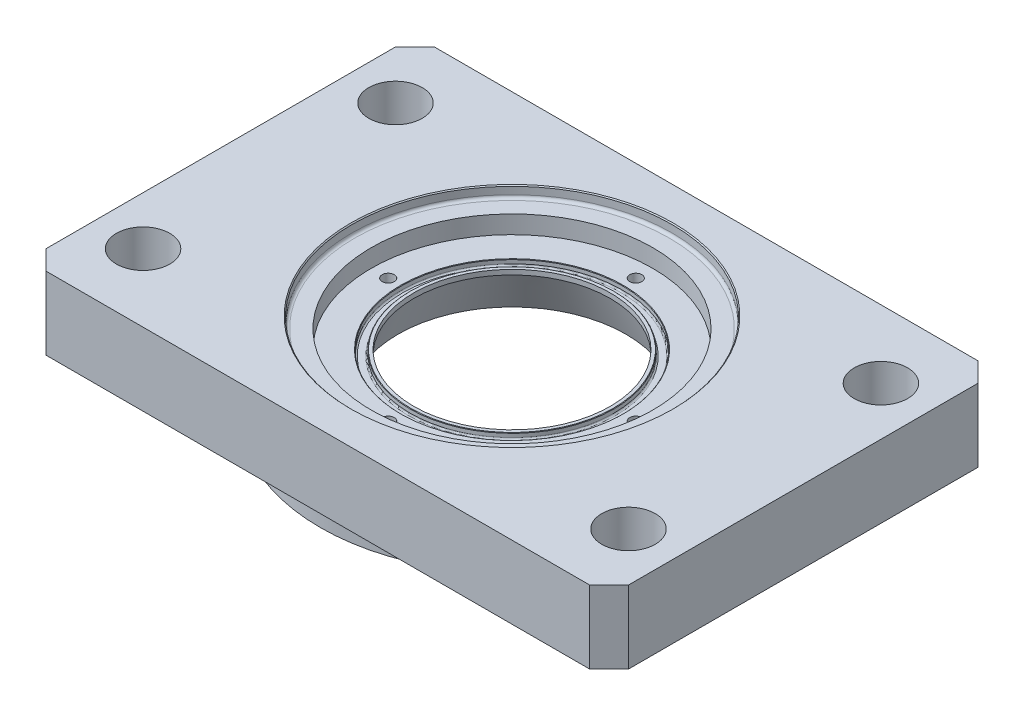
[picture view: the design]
ISO-10303-21;
HEADER;
FILE_DESCRIPTION(('STEP AP214'),'2;1');
FILE_NAME('part.step','',(''),(''),'','','');
FILE_SCHEMA(('AUTOMOTIVE_DESIGN { 1 0 10303 214 1 1 1 1 }'));
ENDSEC;
DATA;
#1=APPLICATION_CONTEXT('core data for automotive mechanical design processes');
#2=APPLICATION_PROTOCOL_DEFINITION('international standard','automotive_design',2000,#1);
#3=PRODUCT_CONTEXT('',#1,'mechanical');
#4=PRODUCT('Part','Part','',(#3));
#5=PRODUCT_RELATED_PRODUCT_CATEGORY('part','',(#4));
#6=PRODUCT_DEFINITION_FORMATION('','',#4);
#7=PRODUCT_DEFINITION_CONTEXT('part definition',#1,'design');
#8=PRODUCT_DEFINITION('design','',#6,#7);
#9=PRODUCT_DEFINITION_SHAPE('','',#8);
#10=(LENGTH_UNIT() NAMED_UNIT(*) SI_UNIT(.MILLI.,.METRE.));
#11=(NAMED_UNIT(*) PLANE_ANGLE_UNIT() SI_UNIT($,.RADIAN.));
#12=(NAMED_UNIT(*) SI_UNIT($,.STERADIAN.) SOLID_ANGLE_UNIT());
#13=UNCERTAINTY_MEASURE_WITH_UNIT(LENGTH_MEASURE(1.E-05),#10,'distance_accuracy_value','');
#14=(GEOMETRIC_REPRESENTATION_CONTEXT(3) GLOBAL_UNCERTAINTY_ASSIGNED_CONTEXT((#13)) GLOBAL_UNIT_ASSIGNED_CONTEXT((#10,
#11,#12)) REPRESENTATION_CONTEXT('',''));
#15=CARTESIAN_POINT('',(0.,0.,0.));
#16=DIRECTION('',(0.,0.,1.));
#17=DIRECTION('',(1.,0.,0.));
#18=AXIS2_PLACEMENT_3D('',#15,#16,#17);
#19=CARTESIAN_POINT('',(25.5,4.386370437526,0.));
#20=DIRECTION('',(0.,1.,0.));
#21=DIRECTION('',(0.,0.,1.));
#22=AXIS2_PLACEMENT_3D('',#19,#20,#21);
#23=CYLINDRICAL_SURFACE('',#22,1.5);
#24=CARTESIAN_POINT('',(25.5,7.,0.));
#25=DIRECTION('',(0.,1.,0.));
#26=DIRECTION('',(0.,0.,1.));
#27=AXIS2_PLACEMENT_3D('',#24,#25,#26);
#28=CIRCLE('',#27,1.5);
#29=CARTESIAN_POINT('',(25.5,7.,1.5));
#30=VERTEX_POINT('',#29);
#31=EDGE_CURVE('P0_E11',#30,#30,#28,.T.);
#32=ORIENTED_EDGE('',*,*,#31,.T.);
#33=EDGE_LOOP('',(#32));
#34=FACE_BOUND('',#33,.T.);
#35=CARTESIAN_POINT('',(25.5,12.,0.));
#36=DIRECTION('',(0.,1.,0.));
#37=DIRECTION('',(0.,0.,1.));
#38=AXIS2_PLACEMENT_3D('',#35,#36,#37);
#39=CIRCLE('',#38,1.5);
#40=CARTESIAN_POINT('',(25.5,12.,1.5));
#41=VERTEX_POINT('',#40);
#42=EDGE_CURVE('P0_E23',#41,#41,#39,.F.);
#43=ORIENTED_EDGE('',*,*,#42,.T.);
#44=EDGE_LOOP('',(#43));
#45=FACE_BOUND('',#44,.T.);
#46=ADVANCED_FACE('P0_F16',(#34,#45),#23,.T.);
#47=CARTESIAN_POINT('',(25.5,7.,0.));
#48=DIRECTION('',(0.,1.,0.));
#49=DIRECTION('',(0.,0.,1.));
#50=AXIS2_PLACEMENT_3D('',#47,#48,#49);
#51=PLANE('',#50);
#52=CARTESIAN_POINT('',(24.25,7.,0.));
#53=CARTESIAN_POINT('',(24.2502025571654,7.,-0.238673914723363));
#54=CARTESIAN_POINT('',(24.337764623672,7.,-0.460118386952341));
#55=CARTESIAN_POINT('',(24.4327647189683,7.,-0.700373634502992));
#56=CARTESIAN_POINT('',(24.6161165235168,7.,-0.883883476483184));
#57=CARTESIAN_POINT('',(24.7987234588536,7.,-1.06664780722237));
#58=CARTESIAN_POINT('',(25.0398816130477,7.,-1.16223537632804));
#59=CARTESIAN_POINT('',(25.2610474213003,7.,-1.24989860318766));
#60=CARTESIAN_POINT('',(25.5,7.,-1.25));
#61=CARTESIAN_POINT('',(25.7379063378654,7.,-1.25010095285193));
#62=CARTESIAN_POINT('',(25.9601183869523,7.,-1.16223537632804));
#63=CARTESIAN_POINT('',(26.2003736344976,7.,-1.06723528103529));
#64=CARTESIAN_POINT('',(26.3838834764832,7.,-0.883883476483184));
#65=CARTESIAN_POINT('',(26.5666478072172,7.,-0.701276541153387));
#66=CARTESIAN_POINT('',(26.662235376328,7.,-0.460118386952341));
#67=CARTESIAN_POINT('',(26.7497969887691,7.,-0.239208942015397));
#68=CARTESIAN_POINT('',(26.75,7.,0.));
#69=B_SPLINE_CURVE_WITH_KNOTS('',2,(#52,#53,#54,#55,#56,#57,#58,#59,#60,#61,#62,#63,#64,#65,#66,
#67,#68),.UNSPECIFIED.,.F.,.F.,(3,2,2,2,2,2,2,2,3),(0.,0.125,0.25,0.375,0.5,0.625,0.75,0.875,
1.),.UNSPECIFIED.);
#70=CARTESIAN_POINT('',(24.25,7.,0.));
#71=VERTEX_POINT('',#70);
#72=CARTESIAN_POINT('',(26.75,7.,0.));
#73=VERTEX_POINT('',#72);
#74=EDGE_CURVE('P0_E27',#71,#73,#69,.T.);
#75=ORIENTED_EDGE('',*,*,#74,.F.);
#76=CARTESIAN_POINT('',(26.75,7.,0.));
#77=CARTESIAN_POINT('',(26.7497974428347,7.,0.238673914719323));
#78=CARTESIAN_POINT('',(26.662235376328,7.,0.460118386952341));
#79=CARTESIAN_POINT('',(26.5672352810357,7.,0.700373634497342));
#80=CARTESIAN_POINT('',(26.3838834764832,7.,0.883883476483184));
#81=CARTESIAN_POINT('',(26.2012765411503,7.,1.06664780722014));
#82=CARTESIAN_POINT('',(25.9601183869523,7.,1.16223537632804));
#83=CARTESIAN_POINT('',(25.7389525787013,7.,1.24989860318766));
#84=CARTESIAN_POINT('',(25.5,7.,1.25));
#85=CARTESIAN_POINT('',(25.2620936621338,7.,1.25010095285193));
#86=CARTESIAN_POINT('',(25.0398816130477,7.,1.16223537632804));
#87=CARTESIAN_POINT('',(24.7996263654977,7.,1.06723528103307));
#88=CARTESIAN_POINT('',(24.6161165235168,7.,0.883883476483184));
#89=CARTESIAN_POINT('',(24.4333521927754,7.,0.701276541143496));
#90=CARTESIAN_POINT('',(24.337764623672,7.,0.460118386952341));
#91=CARTESIAN_POINT('',(24.2502030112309,7.,0.239208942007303));
#92=CARTESIAN_POINT('',(24.25,7.,0.));
#93=B_SPLINE_CURVE_WITH_KNOTS('',2,(#76,#77,#78,#79,#80,#81,#82,#83,#84,#85,#86,#87,#88,#89,#90,
#91,#92),.UNSPECIFIED.,.F.,.F.,(3,2,2,2,2,2,2,2,3),(0.,0.125,0.25,0.375,0.5,0.625,0.75,0.875,
1.),.UNSPECIFIED.);
#94=EDGE_CURVE('P0_E32',#73,#71,#93,.T.);
#95=ORIENTED_EDGE('',*,*,#94,.F.);
#96=EDGE_LOOP('',(#75,#95));
#97=FACE_BOUND('',#96,.T.);
#98=ORIENTED_EDGE('',*,*,#31,.F.);
#99=EDGE_LOOP('',(#98));
#100=FACE_BOUND('',#99,.T.);
#101=ADVANCED_FACE('P0_F17',(#97,#100),#51,.F.);
#102=OPEN_SHELL('',(#46,#101));
#103=SHELL_BASED_SURFACE_MODEL('P0_B1',(#102));
#104=CARTESIAN_POINT('',(0.,12.,0.));
#105=DIRECTION('',(0.,1.,0.));
#106=DIRECTION('',(0.,0.,1.));
#107=AXIS2_PLACEMENT_3D('',#104,#105,#106);
#108=CYLINDRICAL_SURFACE('',#107,21.);
#109=CARTESIAN_POINT('',(0.,11.15,0.));
#110=DIRECTION('',(0.,1.,0.));
#111=DIRECTION('',(0.999942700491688,0.,0.0107049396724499));
#112=AXIS2_PLACEMENT_3D('',#109,#110,#111);
#113=CIRCLE('',#112,21.);
#114=CARTESIAN_POINT('',(20.9987967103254,11.15,0.224803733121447));
#115=VERTEX_POINT('',#114);
#116=EDGE_CURVE('P1_E308',#115,#115,#113,.T.);
#117=ORIENTED_EDGE('',*,*,#116,.T.);
#118=EDGE_LOOP('',(#117));
#119=FACE_BOUND('',#118,.T.);
#120=CARTESIAN_POINT('',(0.,11.9,0.));
#121=DIRECTION('',(0.,-1.,0.));
#122=DIRECTION('',(0.,0.,-1.));
#123=AXIS2_PLACEMENT_3D('',#120,#121,#122);
#124=CIRCLE('',#123,21.);
#125=CARTESIAN_POINT('',(0.,11.9,-21.));
#126=VERTEX_POINT('',#125);
#127=EDGE_CURVE('P1_E116',#126,#126,#124,.F.);
#128=ORIENTED_EDGE('',*,*,#127,.F.);
#129=EDGE_LOOP('',(#128));
#130=FACE_BOUND('',#129,.T.);
#131=ADVANCED_FACE('P1_F16',(#119,#130),#108,.T.);
#132=CARTESIAN_POINT('',(0.,11.15,0.));
#133=DIRECTION('',(0.,1.,0.));
#134=DIRECTION('',(0.999942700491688,0.,0.0107049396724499));
#135=AXIS2_PLACEMENT_3D('',#132,#133,#134);
#136=TOROIDAL_SURFACE('',#135,21.3,0.3);
#137=ORIENTED_EDGE('',*,*,#116,.F.);
#138=EDGE_LOOP('',(#137));
#139=FACE_BOUND('',#138,.T.);
#140=CARTESIAN_POINT('',(0.,10.85,0.));
#141=DIRECTION('',(0.,1.,0.));
#142=DIRECTION('',(-1.,0.,0.));
#143=AXIS2_PLACEMENT_3D('',#140,#141,#142);
#144=CIRCLE('',#143,21.3);
#145=CARTESIAN_POINT('',(21.3,10.85,0.));
#146=VERTEX_POINT('',#145);
#147=CARTESIAN_POINT('',(-21.3,10.85,0.));
#148=VERTEX_POINT('',#147);
#149=EDGE_CURVE('P1_E112',#146,#148,#144,.F.);
#150=ORIENTED_EDGE('',*,*,#149,.F.);
#151=CARTESIAN_POINT('',(0.,10.85,0.));
#152=DIRECTION('',(0.,1.,0.));
#153=DIRECTION('',(1.,0.,0.));
#154=AXIS2_PLACEMENT_3D('',#151,#152,#153);
#155=CIRCLE('',#154,21.3);
#156=EDGE_CURVE('P1_E109',#148,#146,#155,.F.);
#157=ORIENTED_EDGE('',*,*,#156,.F.);
#158=EDGE_LOOP('',(#150,#157));
#159=FACE_BOUND('',#158,.T.);
#160=ADVANCED_FACE('P1_F113',(#139,#159),#136,.F.);
#161=CARTESIAN_POINT('',(0.,11.9,0.));
#162=DIRECTION('',(0.,-1.,0.));
#163=DIRECTION('',(0.,0.,-1.));
#164=AXIS2_PLACEMENT_3D('',#161,#162,#163);
#165=CONICAL_SURFACE('',#164,21.,0.785398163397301);
#166=ORIENTED_EDGE('',*,*,#127,.T.);
#167=EDGE_LOOP('',(#166));
#168=FACE_BOUND('',#167,.T.);
#169=CARTESIAN_POINT('',(0.,12.,0.));
#170=DIRECTION('',(0.,-1.,0.));
#171=DIRECTION('',(0.,0.,-1.));
#172=AXIS2_PLACEMENT_3D('',#169,#170,#171);
#173=CIRCLE('',#172,20.9);
#174=CARTESIAN_POINT('',(0.,12.,-20.9));
#175=VERTEX_POINT('',#174);
#176=EDGE_CURVE('P1_E121',#175,#175,#173,.T.);
#177=ORIENTED_EDGE('',*,*,#176,.T.);
#178=EDGE_LOOP('',(#177));
#179=FACE_BOUND('',#178,.T.);
#180=ADVANCED_FACE('P1_F142',(#168,#179),#165,.T.);
#181=CARTESIAN_POINT('',(0.,10.85,0.));
#182=DIRECTION('',(0.,1.,0.));
#183=DIRECTION('',(0.,0.,1.));
#184=AXIS2_PLACEMENT_3D('',#181,#182,#183);
#185=PLANE('',#184);
#186=ORIENTED_EDGE('',*,*,#149,.T.);
#187=ORIENTED_EDGE('',*,*,#156,.T.);
#188=EDGE_LOOP('',(#186,#187));
#189=FACE_BOUND('',#188,.T.);
#190=CARTESIAN_POINT('',(0.,10.85,0.));
#191=DIRECTION('',(0.,-1.,0.));
#192=DIRECTION('',(1.,0.,0.));
#193=AXIS2_PLACEMENT_3D('',#190,#191,#192);
#194=CIRCLE('',#193,22.55);
#195=CARTESIAN_POINT('',(-22.55,10.85,0.));
#196=VERTEX_POINT('',#195);
#197=CARTESIAN_POINT('',(22.55,10.85,0.));
#198=VERTEX_POINT('',#197);
#199=EDGE_CURVE('P1_E162',#196,#198,#194,.F.);
#200=ORIENTED_EDGE('',*,*,#199,.T.);
#201=CARTESIAN_POINT('',(0.,10.85,0.));
#202=DIRECTION('',(0.,-1.,0.));
#203=DIRECTION('',(-1.,0.,0.));
#204=AXIS2_PLACEMENT_3D('',#201,#202,#203);
#205=CIRCLE('',#204,22.55);
#206=EDGE_CURVE('P1_E161',#198,#196,#205,.F.);
#207=ORIENTED_EDGE('',*,*,#206,.T.);
#208=EDGE_LOOP('',(#200,#207));
#209=FACE_BOUND('',#208,.T.);
#210=ADVANCED_FACE('P1_F119',(#189,#209),#185,.T.);
#211=CARTESIAN_POINT('',(0.,12.,0.));
#212=DIRECTION('',(0.,-1.,0.));
#213=DIRECTION('',(0.,0.,-1.));
#214=AXIS2_PLACEMENT_3D('',#211,#212,#213);
#215=PLANE('',#214);
#216=CARTESIAN_POINT('',(0.,12.,0.));
#217=DIRECTION('',(0.,1.,0.));
#218=DIRECTION('',(0.,0.,1.));
#219=AXIS2_PLACEMENT_3D('',#216,#217,#218);
#220=CIRCLE('',#219,20.25);
#221=CARTESIAN_POINT('',(0.,12.,20.25));
#222=VERTEX_POINT('',#221);
#223=EDGE_CURVE('P1_E166',#222,#222,#220,.F.);
#224=ORIENTED_EDGE('',*,*,#223,.T.);
#225=EDGE_LOOP('',(#224));
#226=FACE_BOUND('',#225,.T.);
#227=ORIENTED_EDGE('',*,*,#176,.F.);
#228=EDGE_LOOP('',(#227));
#229=FACE_BOUND('',#228,.T.);
#230=ADVANCED_FACE('P1_F141',(#226,#229),#215,.F.);
#231=CARTESIAN_POINT('',(0.,11.15,0.));
#232=DIRECTION('',(0.,1.,0.));
#233=DIRECTION('',(0.999902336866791,0.,-0.0139755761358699));
#234=AXIS2_PLACEMENT_3D('',#231,#232,#233);
#235=TOROIDAL_SURFACE('',#234,22.55,0.3);
#236=CARTESIAN_POINT('',(0.,11.15,0.));
#237=DIRECTION('',(0.,1.,0.));
#238=DIRECTION('',(0.,0.,1.));
#239=AXIS2_PLACEMENT_3D('',#236,#237,#238);
#240=CIRCLE('',#239,22.85);
#241=CARTESIAN_POINT('',(0.,11.15,22.85));
#242=VERTEX_POINT('',#241);
#243=EDGE_CURVE('P1_E168',#242,#242,#240,.T.);
#244=ORIENTED_EDGE('',*,*,#243,.T.);
#245=EDGE_LOOP('',(#244));
#246=FACE_BOUND('',#245,.T.);
#247=ORIENTED_EDGE('',*,*,#206,.F.);
#248=ORIENTED_EDGE('',*,*,#199,.F.);
#249=EDGE_LOOP('',(#247,#248));
#250=FACE_BOUND('',#249,.T.);
#251=ADVANCED_FACE('P1_F165',(#246,#250),#235,.F.);
#252=CARTESIAN_POINT('',(0.,2.55,0.));
#253=DIRECTION('',(0.,1.,0.));
#254=DIRECTION('',(0.,0.,1.));
#255=AXIS2_PLACEMENT_3D('',#252,#253,#254);
#256=CYLINDRICAL_SURFACE('',#255,20.25);
#257=CARTESIAN_POINT('',(0.,10.9999999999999,0.));
#258=DIRECTION('',(0.,-1.,0.));
#259=DIRECTION('',(-1.,0.,0.));
#260=AXIS2_PLACEMENT_3D('',#257,#258,#259);
#261=CIRCLE('',#260,20.2499999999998);
#262=CARTESIAN_POINT('',(-20.2499999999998,10.9999999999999,0.));
#263=VERTEX_POINT('',#262);
#264=EDGE_CURVE('P1_E173',#263,#263,#261,.T.);
#265=ORIENTED_EDGE('',*,*,#264,.T.);
#266=EDGE_LOOP('',(#265));
#267=FACE_BOUND('',#266,.T.);
#268=ORIENTED_EDGE('',*,*,#223,.F.);
#269=EDGE_LOOP('',(#268));
#270=FACE_BOUND('',#269,.T.);
#271=ADVANCED_FACE('P1_F273',(#267,#270),#256,.F.);
#272=CARTESIAN_POINT('',(-25.5,5.49999999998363,0.));
#273=DIRECTION('',(0.,1.,0.));
#274=DIRECTION('',(0.,0.,1.));
#275=AXIS2_PLACEMENT_3D('',#272,#273,#274);
#276=CONICAL_SURFACE('',#275,1.24999999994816,1.0297442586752);
#277=CARTESIAN_POINT('',(-25.5,5.5,0.));
#278=DIRECTION('',(0.,1.,0.));
#279=DIRECTION('',(0.,0.,1.));
#280=AXIS2_PLACEMENT_3D('',#277,#278,#279);
#281=CIRCLE('',#280,1.25);
#282=CARTESIAN_POINT('',(-25.5,5.5,1.25));
#283=VERTEX_POINT('',#282);
#284=EDGE_CURVE('P1_E264',#283,#283,#281,.T.);
#285=ORIENTED_EDGE('',*,*,#284,.T.);
#286=EDGE_LOOP('',(#285));
#287=FACE_BOUND('',#286,.T.);
#288=CARTESIAN_POINT('',(-25.4999999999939,4.74892422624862,0.));
#289=VERTEX_POINT('',#288);
#290=VERTEX_LOOP('',#289);
#291=FACE_BOUND('',#290,.T.);
#292=ADVANCED_FACE('P1_F656',(#287,#291),#276,.F.);
#293=CARTESIAN_POINT('',(0.,5.49999999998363,25.5));
#294=DIRECTION('',(0.,1.,0.));
#295=DIRECTION('',(0.,0.,1.));
#296=AXIS2_PLACEMENT_3D('',#293,#294,#295);
#297=CONICAL_SURFACE('',#296,1.24999999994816,1.0297442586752);
#298=CARTESIAN_POINT('',(0.,5.5,25.5));
#299=DIRECTION('',(0.,1.,0.));
#300=DIRECTION('',(0.,0.,1.));
#301=AXIS2_PLACEMENT_3D('',#298,#299,#300);
#302=CIRCLE('',#301,1.25);
#303=CARTESIAN_POINT('',(0.,5.5,26.75));
#304=VERTEX_POINT('',#303);
#305=EDGE_CURVE('P1_E261',#304,#304,#302,.T.);
#306=ORIENTED_EDGE('',*,*,#305,.T.);
#307=EDGE_LOOP('',(#306));
#308=FACE_BOUND('',#307,.T.);
#309=CARTESIAN_POINT('',(0.,4.74892422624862,25.4999999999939));
#310=VERTEX_POINT('',#309);
#311=VERTEX_LOOP('',#310);
#312=FACE_BOUND('',#311,.T.);
#313=ADVANCED_FACE('P1_F652',(#308,#312),#297,.F.);
#314=CARTESIAN_POINT('',(25.5,5.49999999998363,0.));
#315=DIRECTION('',(0.,1.,0.));
#316=DIRECTION('',(0.,0.,1.));
#317=AXIS2_PLACEMENT_3D('',#314,#315,#316);
#318=CONICAL_SURFACE('',#317,1.24999999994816,1.0297442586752);
#319=CARTESIAN_POINT('',(25.5,5.5,0.));
#320=DIRECTION('',(0.,1.,0.));
#321=DIRECTION('',(0.,0.,1.));
#322=AXIS2_PLACEMENT_3D('',#319,#320,#321);
#323=CIRCLE('',#322,1.25);
#324=CARTESIAN_POINT('',(25.5,5.5,1.25));
#325=VERTEX_POINT('',#324);
#326=EDGE_CURVE('P1_E258',#325,#325,#323,.T.);
#327=ORIENTED_EDGE('',*,*,#326,.T.);
#328=EDGE_LOOP('',(#327));
#329=FACE_BOUND('',#328,.T.);
#330=CARTESIAN_POINT('',(25.4999999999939,4.74892422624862,0.));
#331=VERTEX_POINT('',#330);
#332=VERTEX_LOOP('',#331);
#333=FACE_BOUND('',#332,.T.);
#334=ADVANCED_FACE('P1_F655',(#329,#333),#318,.F.);
#335=CARTESIAN_POINT('',(0.,5.49999999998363,-25.5));
#336=DIRECTION('',(0.,1.,0.));
#337=DIRECTION('',(0.,0.,1.));
#338=AXIS2_PLACEMENT_3D('',#335,#336,#337);
#339=CONICAL_SURFACE('',#338,1.24999999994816,1.0297442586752);
#340=CARTESIAN_POINT('',(0.,5.5,-25.5));
#341=DIRECTION('',(0.,1.,0.));
#342=DIRECTION('',(0.,0.,1.));
#343=AXIS2_PLACEMENT_3D('',#340,#341,#342);
#344=CIRCLE('',#343,1.25);
#345=CARTESIAN_POINT('',(0.,5.5,-24.25));
#346=VERTEX_POINT('',#345);
#347=EDGE_CURVE('P1_E255',#346,#346,#344,.T.);
#348=ORIENTED_EDGE('',*,*,#347,.T.);
#349=EDGE_LOOP('',(#348));
#350=FACE_BOUND('',#349,.T.);
#351=CARTESIAN_POINT('',(0.,4.74892422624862,-25.4999999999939));
#352=VERTEX_POINT('',#351);
#353=VERTEX_LOOP('',#352);
#354=FACE_BOUND('',#353,.T.);
#355=ADVANCED_FACE('P1_F414',(#350,#354),#339,.F.);
#356=CARTESIAN_POINT('',(0.,12.,0.));
#357=DIRECTION('',(0.,1.,0.));
#358=DIRECTION('',(0.,0.,1.));
#359=AXIS2_PLACEMENT_3D('',#356,#357,#358);
#360=CYLINDRICAL_SURFACE('',#359,22.85);
#361=ORIENTED_EDGE('',*,*,#243,.F.);
#362=EDGE_LOOP('',(#361));
#363=FACE_BOUND('',#362,.T.);
#364=CARTESIAN_POINT('',(0.,11.9,0.));
#365=DIRECTION('',(0.,1.,0.));
#366=DIRECTION('',(0.,0.,-1.));
#367=AXIS2_PLACEMENT_3D('',#364,#365,#366);
#368=CIRCLE('',#367,22.85);
#369=CARTESIAN_POINT('',(0.,11.9,-22.85));
#370=VERTEX_POINT('',#369);
#371=EDGE_CURVE('P1_E247',#370,#370,#368,.T.);
#372=ORIENTED_EDGE('',*,*,#371,.T.);
#373=EDGE_LOOP('',(#372));
#374=FACE_BOUND('',#373,.T.);
#375=ADVANCED_FACE('P1_F403',(#363,#374),#360,.F.);
#376=CARTESIAN_POINT('',(0.,3.0000000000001,0.));
#377=DIRECTION('',(0.,-1.,0.));
#378=DIRECTION('',(0.,0.,-1.));
#379=AXIS2_PLACEMENT_3D('',#376,#377,#378);
#380=CONICAL_SURFACE('',#379,23.4822098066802,0.38397243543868);
#381=ORIENTED_EDGE('',*,*,#264,.F.);
#382=EDGE_LOOP('',(#381));
#383=FACE_BOUND('',#382,.T.);
#384=CARTESIAN_POINT('',(0.,3.0000000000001,0.));
#385=DIRECTION('',(0.,-1.,0.));
#386=DIRECTION('',(0.,0.,-1.));
#387=AXIS2_PLACEMENT_3D('',#384,#385,#386);
#388=CIRCLE('',#387,23.4822098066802);
#389=CARTESIAN_POINT('',(0.,3.0000000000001,-23.4822098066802));
#390=VERTEX_POINT('',#389);
#391=EDGE_CURVE('P1_E177',#390,#390,#388,.F.);
#392=ORIENTED_EDGE('',*,*,#391,.F.);
#393=EDGE_LOOP('',(#392));
#394=FACE_BOUND('',#393,.T.);
#395=ADVANCED_FACE('P1_F400',(#383,#394),#380,.F.);
#396=CARTESIAN_POINT('',(-25.5,4.386370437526,0.));
#397=DIRECTION('',(0.,1.,0.));
#398=DIRECTION('',(0.,0.,1.));
#399=AXIS2_PLACEMENT_3D('',#396,#397,#398);
#400=CYLINDRICAL_SURFACE('',#399,1.25);
#401=ORIENTED_EDGE('',*,*,#284,.F.);
#402=EDGE_LOOP('',(#401));
#403=FACE_BOUND('',#402,.T.);
#404=CARTESIAN_POINT('',(-25.5,12.,0.));
#405=DIRECTION('',(0.,1.,0.));
#406=DIRECTION('',(0.,0.,1.));
#407=AXIS2_PLACEMENT_3D('',#404,#405,#406);
#408=CIRCLE('',#407,1.25);
#409=CARTESIAN_POINT('',(-25.5,12.,1.25));
#410=VERTEX_POINT('',#409);
#411=EDGE_CURVE('P1_E390',#410,#410,#408,.T.);
#412=ORIENTED_EDGE('',*,*,#411,.T.);
#413=EDGE_LOOP('',(#412));
#414=FACE_BOUND('',#413,.T.);
#415=ADVANCED_FACE('P1_F402',(#403,#414),#400,.F.);
#416=CARTESIAN_POINT('',(0.,4.386370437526,25.5));
#417=DIRECTION('',(0.,1.,0.));
#418=DIRECTION('',(0.,0.,1.));
#419=AXIS2_PLACEMENT_3D('',#416,#417,#418);
#420=CYLINDRICAL_SURFACE('',#419,1.25);
#421=ORIENTED_EDGE('',*,*,#305,.F.);
#422=EDGE_LOOP('',(#421));
#423=FACE_BOUND('',#422,.T.);
#424=CARTESIAN_POINT('',(0.,12.,25.5));
#425=DIRECTION('',(0.,1.,0.));
#426=DIRECTION('',(0.,0.,1.));
#427=AXIS2_PLACEMENT_3D('',#424,#425,#426);
#428=CIRCLE('',#427,1.25);
#429=CARTESIAN_POINT('',(0.,12.,26.75));
#430=VERTEX_POINT('',#429);
#431=EDGE_CURVE('P1_E388',#430,#430,#428,.T.);
#432=ORIENTED_EDGE('',*,*,#431,.T.);
#433=EDGE_LOOP('',(#432));
#434=FACE_BOUND('',#433,.T.);
#435=ADVANCED_FACE('P1_F411',(#423,#434),#420,.F.);
#436=CARTESIAN_POINT('',(25.5,4.386370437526,0.));
#437=DIRECTION('',(0.,1.,0.));
#438=DIRECTION('',(0.,0.,1.));
#439=AXIS2_PLACEMENT_3D('',#436,#437,#438);
#440=CYLINDRICAL_SURFACE('',#439,1.25);
#441=ORIENTED_EDGE('',*,*,#326,.F.);
#442=EDGE_LOOP('',(#441));
#443=FACE_BOUND('',#442,.T.);
#444=CARTESIAN_POINT('',(25.5,12.,0.));
#445=DIRECTION('',(0.,1.,0.));
#446=DIRECTION('',(0.,0.,1.));
#447=AXIS2_PLACEMENT_3D('',#444,#445,#446);
#448=CIRCLE('',#447,1.25);
#449=CARTESIAN_POINT('',(25.5,12.,1.25));
#450=VERTEX_POINT('',#449);
#451=EDGE_CURVE('P1_E385',#450,#450,#448,.T.);
#452=ORIENTED_EDGE('',*,*,#451,.T.);
#453=EDGE_LOOP('',(#452));
#454=FACE_BOUND('',#453,.T.);
#455=ADVANCED_FACE('P1_F633',(#443,#454),#440,.F.);
#456=CARTESIAN_POINT('',(0.,4.386370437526,-25.5));
#457=DIRECTION('',(0.,1.,0.));
#458=DIRECTION('',(0.,0.,1.));
#459=AXIS2_PLACEMENT_3D('',#456,#457,#458);
#460=CYLINDRICAL_SURFACE('',#459,1.25);
#461=ORIENTED_EDGE('',*,*,#347,.F.);
#462=EDGE_LOOP('',(#461));
#463=FACE_BOUND('',#462,.T.);
#464=CARTESIAN_POINT('',(0.,12.,-25.5));
#465=DIRECTION('',(0.,1.,0.));
#466=DIRECTION('',(0.,0.,1.));
#467=AXIS2_PLACEMENT_3D('',#464,#465,#466);
#468=CIRCLE('',#467,1.25);
#469=CARTESIAN_POINT('',(0.,12.,-24.25));
#470=VERTEX_POINT('',#469);
#471=EDGE_CURVE('P1_E382',#470,#470,#468,.T.);
#472=ORIENTED_EDGE('',*,*,#471,.T.);
#473=EDGE_LOOP('',(#472));
#474=FACE_BOUND('',#473,.T.);
#475=ADVANCED_FACE('P1_F629',(#463,#474),#460,.F.);
#476=CARTESIAN_POINT('',(0.,12.,0.));
#477=DIRECTION('',(0.,1.,0.));
#478=DIRECTION('',(-1.,0.,0.));
#479=AXIS2_PLACEMENT_3D('',#476,#477,#478);
#480=CONICAL_SURFACE('',#479,22.95,0.785398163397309);
#481=ORIENTED_EDGE('',*,*,#371,.F.);
#482=EDGE_LOOP('',(#481));
#483=FACE_BOUND('',#482,.T.);
#484=CARTESIAN_POINT('',(0.,12.,0.));
#485=DIRECTION('',(0.,1.,0.));
#486=DIRECTION('',(-1.,0.,0.));
#487=AXIS2_PLACEMENT_3D('',#484,#485,#486);
#488=CIRCLE('',#487,22.95);
#489=CARTESIAN_POINT('',(-22.95,12.,0.));
#490=VERTEX_POINT('',#489);
#491=EDGE_CURVE('P1_E379',#490,#490,#488,.T.);
#492=ORIENTED_EDGE('',*,*,#491,.T.);
#493=EDGE_LOOP('',(#492));
#494=FACE_BOUND('',#493,.T.);
#495=ADVANCED_FACE('P1_F626',(#483,#494),#480,.F.);
#496=CARTESIAN_POINT('',(0.,3.,0.));
#497=DIRECTION('',(0.,-1.,0.));
#498=DIRECTION('',(0.,0.,-1.));
#499=AXIS2_PLACEMENT_3D('',#496,#497,#498);
#500=PLANE('',#499);
#501=ORIENTED_EDGE('',*,*,#391,.T.);
#502=EDGE_LOOP('',(#501));
#503=FACE_BOUND('',#502,.T.);
#504=CARTESIAN_POINT('',(0.,3.,0.));
#505=DIRECTION('',(0.,-1.,0.));
#506=DIRECTION('',(0.,0.,-1.));
#507=AXIS2_PLACEMENT_3D('',#504,#505,#506);
#508=CIRCLE('',#507,38.);
#509=CARTESIAN_POINT('',(0.,3.,-38.));
#510=VERTEX_POINT('',#509);
#511=EDGE_CURVE('P1_E376',#510,#510,#508,.T.);
#512=ORIENTED_EDGE('',*,*,#511,.T.);
#513=EDGE_LOOP('',(#512));
#514=FACE_BOUND('',#513,.T.);
#515=ADVANCED_FACE('P1_F397',(#503,#514),#500,.T.);
#516=CARTESIAN_POINT('',(0.,12.,0.));
#517=DIRECTION('',(0.,-1.,0.));
#518=DIRECTION('',(0.,0.,-1.));
#519=AXIS2_PLACEMENT_3D('',#516,#517,#518);
#520=PLANE('',#519);
#521=ORIENTED_EDGE('',*,*,#491,.F.);
#522=EDGE_LOOP('',(#521));
#523=FACE_BOUND('',#522,.T.);
#524=ORIENTED_EDGE('',*,*,#471,.F.);
#525=EDGE_LOOP('',(#524));
#526=FACE_BOUND('',#525,.T.);
#527=ORIENTED_EDGE('',*,*,#451,.F.);
#528=EDGE_LOOP('',(#527));
#529=FACE_BOUND('',#528,.T.);
#530=ORIENTED_EDGE('',*,*,#431,.F.);
#531=EDGE_LOOP('',(#530));
#532=FACE_BOUND('',#531,.T.);
#533=ORIENTED_EDGE('',*,*,#411,.F.);
#534=EDGE_LOOP('',(#533));
#535=FACE_BOUND('',#534,.T.);
#536=CARTESIAN_POINT('',(0.,12.,0.));
#537=DIRECTION('',(0.,-1.,0.));
#538=DIRECTION('',(0.,0.,-1.));
#539=AXIS2_PLACEMENT_3D('',#536,#537,#538);
#540=CIRCLE('',#539,29.);
#541=CARTESIAN_POINT('',(0.,12.,-29.));
#542=VERTEX_POINT('',#541);
#543=EDGE_CURVE('P1_E373',#542,#542,#540,.F.);
#544=ORIENTED_EDGE('',*,*,#543,.T.);
#545=EDGE_LOOP('',(#544));
#546=FACE_BOUND('',#545,.T.);
#547=ADVANCED_FACE('P1_F614',(#523,#526,#529,#532,#535,#546),#520,.F.);
#548=CARTESIAN_POINT('',(0.,0.,0.));
#549=DIRECTION('',(0.,-1.,0.));
#550=DIRECTION('',(0.,0.,-1.));
#551=AXIS2_PLACEMENT_3D('',#548,#549,#550);
#552=CYLINDRICAL_SURFACE('',#551,38.);
#553=ORIENTED_EDGE('',*,*,#511,.F.);
#554=EDGE_LOOP('',(#553));
#555=FACE_BOUND('',#554,.T.);
#556=CARTESIAN_POINT('',(0.,0.,0.));
#557=DIRECTION('',(0.,-1.,0.));
#558=DIRECTION('',(0.,0.,-1.));
#559=AXIS2_PLACEMENT_3D('',#556,#557,#558);
#560=CIRCLE('',#559,38.);
#561=CARTESIAN_POINT('',(0.,0.,-38.));
#562=VERTEX_POINT('',#561);
#563=EDGE_CURVE('P1_E370',#562,#562,#560,.T.);
#564=ORIENTED_EDGE('',*,*,#563,.T.);
#565=EDGE_LOOP('',(#564));
#566=FACE_BOUND('',#565,.T.);
#567=ADVANCED_FACE('P1_F609',(#555,#566),#552,.F.);
#568=CARTESIAN_POINT('',(0.,18.,0.));
#569=DIRECTION('',(0.,-1.,0.));
#570=DIRECTION('',(0.,0.,-1.));
#571=AXIS2_PLACEMENT_3D('',#568,#569,#570);
#572=CYLINDRICAL_SURFACE('',#571,29.);
#573=ORIENTED_EDGE('',*,*,#543,.F.);
#574=EDGE_LOOP('',(#573));
#575=FACE_BOUND('',#574,.T.);
#576=CARTESIAN_POINT('',(0.,15.7,0.));
#577=DIRECTION('',(0.,-1.,0.));
#578=DIRECTION('',(0.,0.,-1.));
#579=AXIS2_PLACEMENT_3D('',#576,#577,#578);
#580=CIRCLE('',#579,29.);
#581=CARTESIAN_POINT('',(0.,15.7,-29.));
#582=VERTEX_POINT('',#581);
#583=EDGE_CURVE('P1_E367',#582,#582,#580,.T.);
#584=ORIENTED_EDGE('',*,*,#583,.F.);
#585=EDGE_LOOP('',(#584));
#586=FACE_BOUND('',#585,.T.);
#587=ADVANCED_FACE('P1_F604',(#575,#586),#572,.F.);
#588=CARTESIAN_POINT('',(0.,0.,0.));
#589=DIRECTION('',(0.,1.,0.));
#590=DIRECTION('',(0.,0.,1.));
#591=AXIS2_PLACEMENT_3D('',#588,#589,#590);
#592=PLANE('',#591);
#593=ORIENTED_EDGE('',*,*,#563,.F.);
#594=EDGE_LOOP('',(#593));
#595=FACE_BOUND('',#594,.T.);
#596=CARTESIAN_POINT('',(0.,0.,0.));
#597=DIRECTION('',(0.,-1.,0.));
#598=DIRECTION('',(0.,0.,-1.));
#599=AXIS2_PLACEMENT_3D('',#596,#597,#598);
#600=CIRCLE('',#599,39.5);
#601=CARTESIAN_POINT('',(0.,0.,-39.5));
#602=VERTEX_POINT('',#601);
#603=EDGE_CURVE('P1_E364',#602,#602,#600,.F.);
#604=ORIENTED_EDGE('',*,*,#603,.F.);
#605=EDGE_LOOP('',(#604));
#606=FACE_BOUND('',#605,.T.);
#607=ADVANCED_FACE('P1_F230',(#595,#606),#592,.F.);
#608=CARTESIAN_POINT('',(0.,15.7,0.));
#609=DIRECTION('',(0.,1.,0.));
#610=DIRECTION('',(0.,0.,1.));
#611=AXIS2_PLACEMENT_3D('',#608,#609,#610);
#612=PLANE('',#611);
#613=ORIENTED_EDGE('',*,*,#583,.T.);
#614=EDGE_LOOP('',(#613));
#615=FACE_BOUND('',#614,.T.);
#616=CARTESIAN_POINT('',(0.,15.7,0.));
#617=DIRECTION('',(0.,-1.,0.));
#618=DIRECTION('',(1.,0.,0.));
#619=AXIS2_PLACEMENT_3D('',#616,#617,#618);
#620=CIRCLE('',#619,32.4);
#621=CARTESIAN_POINT('',(-32.4,15.7,0.));
#622=VERTEX_POINT('',#621);
#623=CARTESIAN_POINT('',(32.4,15.7,0.));
#624=VERTEX_POINT('',#623);
#625=EDGE_CURVE('P1_E185',#622,#624,#620,.F.);
#626=ORIENTED_EDGE('',*,*,#625,.T.);
#627=CARTESIAN_POINT('',(0.,15.7,0.));
#628=DIRECTION('',(0.,-1.,0.));
#629=DIRECTION('',(-1.,0.,0.));
#630=AXIS2_PLACEMENT_3D('',#627,#628,#629);
#631=CIRCLE('',#630,32.4);
#632=EDGE_CURVE('P1_E243',#624,#622,#631,.F.);
#633=ORIENTED_EDGE('',*,*,#632,.T.);
#634=EDGE_LOOP('',(#626,#633));
#635=FACE_BOUND('',#634,.T.);
#636=ADVANCED_FACE('P1_F219',(#615,#635),#612,.T.);
#637=CARTESIAN_POINT('',(0.,0.,0.));
#638=DIRECTION('',(0.,-1.,0.));
#639=DIRECTION('',(0.,0.,-1.));
#640=AXIS2_PLACEMENT_3D('',#637,#638,#639);
#641=CYLINDRICAL_SURFACE('',#640,39.5);
#642=CARTESIAN_POINT('',(0.,3.,0.));
#643=DIRECTION('',(0.,-1.,0.));
#644=DIRECTION('',(0.,0.,-1.));
#645=AXIS2_PLACEMENT_3D('',#642,#643,#644);
#646=CIRCLE('',#645,39.5);
#647=CARTESIAN_POINT('',(0.,3.,-39.5));
#648=VERTEX_POINT('',#647);
#649=EDGE_CURVE('P1_E361',#648,#648,#646,.F.);
#650=ORIENTED_EDGE('',*,*,#649,.F.);
#651=EDGE_LOOP('',(#650));
#652=FACE_BOUND('',#651,.T.);
#653=ORIENTED_EDGE('',*,*,#603,.T.);
#654=EDGE_LOOP('',(#653));
#655=FACE_BOUND('',#654,.T.);
#656=ADVANCED_FACE('P1_F229',(#652,#655),#641,.T.);
#657=CARTESIAN_POINT('',(-50.,3.,26.));
#658=DIRECTION('',(0.,1.,0.));
#659=DIRECTION('',(0.,0.,1.));
#660=AXIS2_PLACEMENT_3D('',#657,#658,#659);
#661=CYLINDRICAL_SURFACE('',#660,8.5);
#662=CARTESIAN_POINT('',(-50.,8.,26.));
#663=DIRECTION('',(0.,1.,0.));
#664=DIRECTION('',(0.,0.,1.));
#665=AXIS2_PLACEMENT_3D('',#662,#663,#664);
#666=CIRCLE('',#665,8.5);
#667=CARTESIAN_POINT('',(-50.,8.,34.5));
#668=VERTEX_POINT('',#667);
#669=EDGE_CURVE('P1_E346',#668,#668,#666,.T.);
#670=ORIENTED_EDGE('',*,*,#669,.T.);
#671=EDGE_LOOP('',(#670));
#672=FACE_BOUND('',#671,.T.);
#673=CARTESIAN_POINT('',(-50.,3.,26.));
#674=DIRECTION('',(0.,1.,0.));
#675=DIRECTION('',(0.,0.,1.));
#676=AXIS2_PLACEMENT_3D('',#673,#674,#675);
#677=CIRCLE('',#676,8.5);
#678=CARTESIAN_POINT('',(-50.,3.,34.5));
#679=VERTEX_POINT('',#678);
#680=EDGE_CURVE('P1_E352',#679,#679,#677,.T.);
#681=ORIENTED_EDGE('',*,*,#680,.F.);
#682=EDGE_LOOP('',(#681));
#683=FACE_BOUND('',#682,.T.);
#684=ADVANCED_FACE('P1_F503',(#672,#683),#661,.F.);
#685=CARTESIAN_POINT('',(50.,3.,-26.));
#686=DIRECTION('',(0.,1.,0.));
#687=DIRECTION('',(0.,0.,1.));
#688=AXIS2_PLACEMENT_3D('',#685,#686,#687);
#689=CYLINDRICAL_SURFACE('',#688,8.5);
#690=CARTESIAN_POINT('',(50.,8.,-26.));
#691=DIRECTION('',(0.,1.,0.));
#692=DIRECTION('',(0.,0.,1.));
#693=AXIS2_PLACEMENT_3D('',#690,#691,#692);
#694=CIRCLE('',#693,8.5);
#695=CARTESIAN_POINT('',(50.,8.,-17.5));
#696=VERTEX_POINT('',#695);
#697=EDGE_CURVE('P1_E343',#696,#696,#694,.T.);
#698=ORIENTED_EDGE('',*,*,#697,.T.);
#699=EDGE_LOOP('',(#698));
#700=FACE_BOUND('',#699,.T.);
#701=CARTESIAN_POINT('',(50.,3.,-26.));
#702=DIRECTION('',(0.,1.,0.));
#703=DIRECTION('',(0.,0.,1.));
#704=AXIS2_PLACEMENT_3D('',#701,#702,#703);
#705=CIRCLE('',#704,8.5);
#706=CARTESIAN_POINT('',(50.,3.,-17.5));
#707=VERTEX_POINT('',#706);
#708=EDGE_CURVE('P1_E358',#707,#707,#705,.T.);
#709=ORIENTED_EDGE('',*,*,#708,.F.);
#710=EDGE_LOOP('',(#709));
#711=FACE_BOUND('',#710,.T.);
#712=ADVANCED_FACE('P1_F506',(#700,#711),#689,.F.);
#713=CARTESIAN_POINT('',(-50.,3.,-26.));
#714=DIRECTION('',(0.,1.,0.));
#715=DIRECTION('',(0.,0.,1.));
#716=AXIS2_PLACEMENT_3D('',#713,#714,#715);
#717=CYLINDRICAL_SURFACE('',#716,8.5);
#718=CARTESIAN_POINT('',(-50.,8.,-26.));
#719=DIRECTION('',(0.,1.,0.));
#720=DIRECTION('',(0.,0.,1.));
#721=AXIS2_PLACEMENT_3D('',#718,#719,#720);
#722=CIRCLE('',#721,8.5);
#723=CARTESIAN_POINT('',(-50.,8.,-17.5));
#724=VERTEX_POINT('',#723);
#725=EDGE_CURVE('P1_E340',#724,#724,#722,.T.);
#726=ORIENTED_EDGE('',*,*,#725,.T.);
#727=EDGE_LOOP('',(#726));
#728=FACE_BOUND('',#727,.T.);
#729=CARTESIAN_POINT('',(-50.,3.,-26.));
#730=DIRECTION('',(0.,1.,0.));
#731=DIRECTION('',(0.,0.,1.));
#732=AXIS2_PLACEMENT_3D('',#729,#730,#731);
#733=CIRCLE('',#732,8.5);
#734=CARTESIAN_POINT('',(-50.,3.,-17.5));
#735=VERTEX_POINT('',#734);
#736=EDGE_CURVE('P1_E355',#735,#735,#733,.T.);
#737=ORIENTED_EDGE('',*,*,#736,.F.);
#738=EDGE_LOOP('',(#737));
#739=FACE_BOUND('',#738,.T.);
#740=ADVANCED_FACE('P1_F774',(#728,#739),#717,.F.);
#741=CARTESIAN_POINT('',(50.,3.,26.));
#742=DIRECTION('',(0.,1.,0.));
#743=DIRECTION('',(0.,0.,1.));
#744=AXIS2_PLACEMENT_3D('',#741,#742,#743);
#745=CYLINDRICAL_SURFACE('',#744,8.5);
#746=CARTESIAN_POINT('',(50.,8.,26.));
#747=DIRECTION('',(0.,1.,0.));
#748=DIRECTION('',(0.,0.,1.));
#749=AXIS2_PLACEMENT_3D('',#746,#747,#748);
#750=CIRCLE('',#749,8.5);
#751=CARTESIAN_POINT('',(50.,8.,34.5));
#752=VERTEX_POINT('',#751);
#753=EDGE_CURVE('P1_E337',#752,#752,#750,.T.);
#754=ORIENTED_EDGE('',*,*,#753,.T.);
#755=EDGE_LOOP('',(#754));
#756=FACE_BOUND('',#755,.T.);
#757=CARTESIAN_POINT('',(50.,3.,26.));
#758=DIRECTION('',(0.,1.,0.));
#759=DIRECTION('',(0.,0.,1.));
#760=AXIS2_PLACEMENT_3D('',#757,#758,#759);
#761=CIRCLE('',#760,8.5);
#762=CARTESIAN_POINT('',(50.,3.,34.5));
#763=VERTEX_POINT('',#762);
#764=EDGE_CURVE('P1_E349',#763,#763,#761,.T.);
#765=ORIENTED_EDGE('',*,*,#764,.F.);
#766=EDGE_LOOP('',(#765));
#767=FACE_BOUND('',#766,.T.);
#768=ADVANCED_FACE('P1_F201',(#756,#767),#745,.F.);
#769=CARTESIAN_POINT('',(0.,16.3,0.));
#770=DIRECTION('',(0.,1.,0.));
#771=DIRECTION('',(-0.999953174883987,0.,0.00967719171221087));
#772=AXIS2_PLACEMENT_3D('',#769,#770,#771);
#773=TOROIDAL_SURFACE('',#772,32.4,0.6);
#774=CARTESIAN_POINT('',(0.,16.3,0.));
#775=DIRECTION('',(0.,1.,0.));
#776=DIRECTION('',(0.,0.,1.));
#777=AXIS2_PLACEMENT_3D('',#774,#775,#776);
#778=CIRCLE('',#777,33.);
#779=CARTESIAN_POINT('',(0.,16.3,33.));
#780=VERTEX_POINT('',#779);
#781=EDGE_CURVE('P1_E210',#780,#780,#778,.T.);
#782=ORIENTED_EDGE('',*,*,#781,.T.);
#783=EDGE_LOOP('',(#782));
#784=FACE_BOUND('',#783,.T.);
#785=ORIENTED_EDGE('',*,*,#625,.F.);
#786=ORIENTED_EDGE('',*,*,#632,.F.);
#787=EDGE_LOOP('',(#785,#786));
#788=FACE_BOUND('',#787,.T.);
#789=ADVANCED_FACE('P1_F189',(#784,#788),#773,.F.);
#790=CARTESIAN_POINT('',(0.,3.,0.));
#791=DIRECTION('',(0.,-1.,0.));
#792=DIRECTION('',(0.,0.,-1.));
#793=AXIS2_PLACEMENT_3D('',#790,#791,#792);
#794=PLANE('',#793);
#795=ORIENTED_EDGE('',*,*,#764,.T.);
#796=EDGE_LOOP('',(#795));
#797=FACE_BOUND('',#796,.T.);
#798=ORIENTED_EDGE('',*,*,#680,.T.);
#799=EDGE_LOOP('',(#798));
#800=FACE_BOUND('',#799,.T.);
#801=ORIENTED_EDGE('',*,*,#736,.T.);
#802=EDGE_LOOP('',(#801));
#803=FACE_BOUND('',#802,.T.);
#804=ORIENTED_EDGE('',*,*,#708,.T.);
#805=EDGE_LOOP('',(#804));
#806=FACE_BOUND('',#805,.T.);
#807=ORIENTED_EDGE('',*,*,#649,.T.);
#808=EDGE_LOOP('',(#807));
#809=FACE_BOUND('',#808,.T.);
#810=DIRECTION('',(0.,0.,1.));
#811=VECTOR('',#810,1.);
#812=CARTESIAN_POINT('',(-60.,3.,-40.));
#813=LINE('',#812,#811);
#814=CARTESIAN_POINT('',(-60.,3.,-36.));
#815=VERTEX_POINT('',#814);
#816=CARTESIAN_POINT('',(-60.,3.,36.));
#817=VERTEX_POINT('',#816);
#818=EDGE_CURVE('P1_E518',#815,#817,#813,.T.);
#819=ORIENTED_EDGE('',*,*,#818,.F.);
#820=DIRECTION('',(-0.707106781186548,0.,0.707106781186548));
#821=VECTOR('',#820,1.);
#822=CARTESIAN_POINT('',(-58.,3.,-38.));
#823=LINE('',#822,#821);
#824=CARTESIAN_POINT('',(-56.,3.,-40.));
#825=VERTEX_POINT('',#824);
#826=EDGE_CURVE('P1_E336',#825,#815,#823,.T.);
#827=ORIENTED_EDGE('',*,*,#826,.F.);
#828=DIRECTION('',(-1.,0.,0.));
#829=VECTOR('',#828,1.);
#830=CARTESIAN_POINT('',(60.,3.,-40.));
#831=LINE('',#830,#829);
#832=CARTESIAN_POINT('',(56.,3.,-40.));
#833=VERTEX_POINT('',#832);
#834=EDGE_CURVE('P1_E532',#833,#825,#831,.T.);
#835=ORIENTED_EDGE('',*,*,#834,.F.);
#836=DIRECTION('',(-0.707106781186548,0.,-0.707106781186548));
#837=VECTOR('',#836,1.);
#838=CARTESIAN_POINT('',(58.,3.,-38.));
#839=LINE('',#838,#837);
#840=CARTESIAN_POINT('',(60.,3.,-36.));
#841=VERTEX_POINT('',#840);
#842=EDGE_CURVE('P1_E543',#841,#833,#839,.T.);
#843=ORIENTED_EDGE('',*,*,#842,.F.);
#844=DIRECTION('',(0.,0.,-1.));
#845=VECTOR('',#844,1.);
#846=CARTESIAN_POINT('',(60.,3.,40.));
#847=LINE('',#846,#845);
#848=CARTESIAN_POINT('',(60.,3.,36.));
#849=VERTEX_POINT('',#848);
#850=EDGE_CURVE('P1_E551',#849,#841,#847,.T.);
#851=ORIENTED_EDGE('',*,*,#850,.F.);
#852=DIRECTION('',(0.707106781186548,0.,-0.707106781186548));
#853=VECTOR('',#852,1.);
#854=CARTESIAN_POINT('',(58.,3.,38.));
#855=LINE('',#854,#853);
#856=CARTESIAN_POINT('',(56.,3.,40.));
#857=VERTEX_POINT('',#856);
#858=EDGE_CURVE('P1_E553',#857,#849,#855,.T.);
#859=ORIENTED_EDGE('',*,*,#858,.F.);
#860=DIRECTION('',(1.,0.,0.));
#861=VECTOR('',#860,1.);
#862=CARTESIAN_POINT('',(-60.,3.,40.));
#863=LINE('',#862,#861);
#864=CARTESIAN_POINT('',(-56.,3.,40.));
#865=VERTEX_POINT('',#864);
#866=EDGE_CURVE('P1_E562',#865,#857,#863,.T.);
#867=ORIENTED_EDGE('',*,*,#866,.F.);
#868=DIRECTION('',(0.707106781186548,0.,0.707106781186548));
#869=VECTOR('',#868,1.);
#870=CARTESIAN_POINT('',(-58.,3.,38.));
#871=LINE('',#870,#869);
#872=EDGE_CURVE('P1_E523',#817,#865,#871,.T.);
#873=ORIENTED_EDGE('',*,*,#872,.F.);
#874=EDGE_LOOP('',(#819,#827,#835,#843,#851,#859,#867,#873));
#875=FACE_BOUND('',#874,.T.);
#876=ADVANCED_FACE('P1_F200',(#797,#800,#803,#806,#809,#875),#794,.T.);
#877=CARTESIAN_POINT('',(-50.,8.,26.));
#878=DIRECTION('',(0.,1.,0.));
#879=DIRECTION('',(0.,0.,1.));
#880=AXIS2_PLACEMENT_3D('',#877,#878,#879);
#881=PLANE('',#880);
#882=CARTESIAN_POINT('',(-50.,8.,26.));
#883=DIRECTION('',(0.,1.,0.));
#884=DIRECTION('',(0.,0.,1.));
#885=AXIS2_PLACEMENT_3D('',#882,#883,#884);
#886=CIRCLE('',#885,5.5);
#887=CARTESIAN_POINT('',(-50.,8.,31.5));
#888=VERTEX_POINT('',#887);
#889=EDGE_CURVE('P1_E333',#888,#888,#886,.T.);
#890=ORIENTED_EDGE('',*,*,#889,.T.);
#891=EDGE_LOOP('',(#890));
#892=FACE_BOUND('',#891,.T.);
#893=ORIENTED_EDGE('',*,*,#669,.F.);
#894=EDGE_LOOP('',(#893));
#895=FACE_BOUND('',#894,.T.);
#896=ADVANCED_FACE('P1_F491',(#892,#895),#881,.F.);
#897=CARTESIAN_POINT('',(50.,8.,-26.));
#898=DIRECTION('',(0.,1.,0.));
#899=DIRECTION('',(0.,0.,1.));
#900=AXIS2_PLACEMENT_3D('',#897,#898,#899);
#901=PLANE('',#900);
#902=CARTESIAN_POINT('',(50.,8.,-26.));
#903=DIRECTION('',(0.,1.,0.));
#904=DIRECTION('',(0.,0.,1.));
#905=AXIS2_PLACEMENT_3D('',#902,#903,#904);
#906=CIRCLE('',#905,5.5);
#907=CARTESIAN_POINT('',(50.,8.,-20.5));
#908=VERTEX_POINT('',#907);
#909=EDGE_CURVE('P1_E330',#908,#908,#906,.T.);
#910=ORIENTED_EDGE('',*,*,#909,.T.);
#911=EDGE_LOOP('',(#910));
#912=FACE_BOUND('',#911,.T.);
#913=ORIENTED_EDGE('',*,*,#697,.F.);
#914=EDGE_LOOP('',(#913));
#915=FACE_BOUND('',#914,.T.);
#916=ADVANCED_FACE('P1_F488',(#912,#915),#901,.F.);
#917=CARTESIAN_POINT('',(-50.,8.,-26.));
#918=DIRECTION('',(0.,1.,0.));
#919=DIRECTION('',(0.,0.,1.));
#920=AXIS2_PLACEMENT_3D('',#917,#918,#919);
#921=PLANE('',#920);
#922=CARTESIAN_POINT('',(-50.,8.,-26.));
#923=DIRECTION('',(0.,1.,0.));
#924=DIRECTION('',(0.,0.,1.));
#925=AXIS2_PLACEMENT_3D('',#922,#923,#924);
#926=CIRCLE('',#925,5.5);
#927=CARTESIAN_POINT('',(-50.,8.,-20.5));
#928=VERTEX_POINT('',#927);
#929=EDGE_CURVE('P1_E327',#928,#928,#926,.T.);
#930=ORIENTED_EDGE('',*,*,#929,.T.);
#931=EDGE_LOOP('',(#930));
#932=FACE_BOUND('',#931,.T.);
#933=ORIENTED_EDGE('',*,*,#725,.F.);
#934=EDGE_LOOP('',(#933));
#935=FACE_BOUND('',#934,.T.);
#936=ADVANCED_FACE('P1_F484',(#932,#935),#921,.F.);
#937=CARTESIAN_POINT('',(50.,8.,26.));
#938=DIRECTION('',(0.,1.,0.));
#939=DIRECTION('',(0.,0.,1.));
#940=AXIS2_PLACEMENT_3D('',#937,#938,#939);
#941=PLANE('',#940);
#942=CARTESIAN_POINT('',(50.,8.,26.));
#943=DIRECTION('',(0.,1.,0.));
#944=DIRECTION('',(0.,0.,1.));
#945=AXIS2_PLACEMENT_3D('',#942,#943,#944);
#946=CIRCLE('',#945,5.5);
#947=CARTESIAN_POINT('',(50.,8.,31.5));
#948=VERTEX_POINT('',#947);
#949=EDGE_CURVE('P1_E323',#948,#948,#946,.T.);
#950=ORIENTED_EDGE('',*,*,#949,.T.);
#951=EDGE_LOOP('',(#950));
#952=FACE_BOUND('',#951,.T.);
#953=ORIENTED_EDGE('',*,*,#753,.F.);
#954=EDGE_LOOP('',(#953));
#955=FACE_BOUND('',#954,.T.);
#956=ADVANCED_FACE('P1_F480',(#952,#955),#941,.F.);
#957=CARTESIAN_POINT('',(0.,18.,0.));
#958=DIRECTION('',(0.,1.,0.));
#959=DIRECTION('',(0.,0.,1.));
#960=AXIS2_PLACEMENT_3D('',#957,#958,#959);
#961=CYLINDRICAL_SURFACE('',#960,33.);
#962=CARTESIAN_POINT('',(0.,17.8,-6.708615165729E-13));
#963=DIRECTION('',(0.,1.,0.));
#964=DIRECTION('',(0.,0.,-1.));
#965=AXIS2_PLACEMENT_3D('',#962,#963,#964);
#966=CIRCLE('',#965,33.);
#967=CARTESIAN_POINT('',(0.,17.8,-33.0000000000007));
#968=VERTEX_POINT('',#967);
#969=EDGE_CURVE('P1_E326',#968,#968,#966,.T.);
#970=ORIENTED_EDGE('',*,*,#969,.T.);
#971=EDGE_LOOP('',(#970));
#972=FACE_BOUND('',#971,.T.);
#973=ORIENTED_EDGE('',*,*,#781,.F.);
#974=EDGE_LOOP('',(#973));
#975=FACE_BOUND('',#974,.T.);
#976=ADVANCED_FACE('P1_F476',(#972,#975),#961,.F.);
#977=CARTESIAN_POINT('',(-60.,0.,-40.));
#978=DIRECTION('',(-1.,0.,0.));
#979=DIRECTION('',(0.,0.,1.));
#980=AXIS2_PLACEMENT_3D('',#977,#978,#979);
#981=PLANE('',#980);
#982=DIRECTION('',(0.,0.,1.));
#983=VECTOR('',#982,1.);
#984=CARTESIAN_POINT('',(-60.,18.,0.));
#985=LINE('',#984,#983);
#986=CARTESIAN_POINT('',(-60.,18.,-36.));
#987=VERTEX_POINT('',#986);
#988=CARTESIAN_POINT('',(-60.,18.,36.));
#989=VERTEX_POINT('',#988);
#990=EDGE_CURVE('P1_E530',#987,#989,#985,.T.);
#991=ORIENTED_EDGE('',*,*,#990,.F.);
#992=DIRECTION('',(0.,1.,0.));
#993=VECTOR('',#992,1.);
#994=CARTESIAN_POINT('',(-60.,10.5,-36.));
#995=LINE('',#994,#993);
#996=EDGE_CURVE('P1_E528',#815,#987,#995,.T.);
#997=ORIENTED_EDGE('',*,*,#996,.F.);
#998=ORIENTED_EDGE('',*,*,#818,.T.);
#999=DIRECTION('',(0.,1.,0.));
#1000=VECTOR('',#999,1.);
#1001=CARTESIAN_POINT('',(-60.,10.5,36.));
#1002=LINE('',#1001,#1000);
#1003=EDGE_CURVE('P1_E525',#989,#817,#1002,.F.);
#1004=ORIENTED_EDGE('',*,*,#1003,.F.);
#1005=EDGE_LOOP('',(#991,#997,#998,#1004));
#1006=FACE_BOUND('',#1005,.T.);
#1007=ADVANCED_FACE('P1_F472',(#1006),#981,.T.);
#1008=CARTESIAN_POINT('',(-58.,10.5,38.));
#1009=DIRECTION('',(-0.707106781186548,0.,0.707106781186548));
#1010=DIRECTION('',(0.707106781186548,0.,0.707106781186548));
#1011=AXIS2_PLACEMENT_3D('',#1008,#1009,#1010);
#1012=PLANE('',#1011);
#1013=ORIENTED_EDGE('',*,*,#1003,.T.);
#1014=ORIENTED_EDGE('',*,*,#872,.T.);
#1015=DIRECTION('',(0.,1.,0.));
#1016=VECTOR('',#1015,1.);
#1017=CARTESIAN_POINT('',(-56.,0.,40.));
#1018=LINE('',#1017,#1016);
#1019=CARTESIAN_POINT('',(-56.,18.,40.));
#1020=VERTEX_POINT('',#1019);
#1021=EDGE_CURVE('P1_E559',#1020,#865,#1018,.F.);
#1022=ORIENTED_EDGE('',*,*,#1021,.F.);
#1023=DIRECTION('',(0.707106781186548,0.,0.707106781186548));
#1024=VECTOR('',#1023,1.);
#1025=CARTESIAN_POINT('',(-60.,18.,36.));
#1026=LINE('',#1025,#1024);
#1027=EDGE_CURVE('P1_E567',#989,#1020,#1026,.T.);
#1028=ORIENTED_EDGE('',*,*,#1027,.F.);
#1029=EDGE_LOOP('',(#1013,#1014,#1022,#1028));
#1030=FACE_BOUND('',#1029,.T.);
#1031=ADVANCED_FACE('P1_F468',(#1030),#1012,.T.);
#1032=CARTESIAN_POINT('',(-60.,0.,40.));
#1033=DIRECTION('',(0.,0.,1.));
#1034=DIRECTION('',(1.,0.,0.));
#1035=AXIS2_PLACEMENT_3D('',#1032,#1033,#1034);
#1036=PLANE('',#1035);
#1037=DIRECTION('',(1.,0.,0.));
#1038=VECTOR('',#1037,1.);
#1039=CARTESIAN_POINT('',(0.,18.,40.));
#1040=LINE('',#1039,#1038);
#1041=CARTESIAN_POINT('',(56.,18.,40.));
#1042=VERTEX_POINT('',#1041);
#1043=EDGE_CURVE('P1_E570',#1020,#1042,#1040,.T.);
#1044=ORIENTED_EDGE('',*,*,#1043,.F.);
#1045=ORIENTED_EDGE('',*,*,#1021,.T.);
#1046=ORIENTED_EDGE('',*,*,#866,.T.);
#1047=DIRECTION('',(0.,1.,0.));
#1048=VECTOR('',#1047,1.);
#1049=CARTESIAN_POINT('',(56.,10.5,40.));
#1050=LINE('',#1049,#1048);
#1051=EDGE_CURVE('P1_E556',#1042,#857,#1050,.F.);
#1052=ORIENTED_EDGE('',*,*,#1051,.F.);
#1053=EDGE_LOOP('',(#1044,#1045,#1046,#1052));
#1054=FACE_BOUND('',#1053,.T.);
#1055=ADVANCED_FACE('P1_F464',(#1054),#1036,.T.);
#1056=CARTESIAN_POINT('',(58.,10.5,38.));
#1057=DIRECTION('',(0.707106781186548,0.,0.707106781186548));
#1058=DIRECTION('',(0.707106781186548,0.,-0.707106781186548));
#1059=AXIS2_PLACEMENT_3D('',#1056,#1057,#1058);
#1060=PLANE('',#1059);
#1061=ORIENTED_EDGE('',*,*,#1051,.T.);
#1062=ORIENTED_EDGE('',*,*,#858,.T.);
#1063=DIRECTION('',(0.,1.,0.));
#1064=VECTOR('',#1063,1.);
#1065=CARTESIAN_POINT('',(60.,0.,36.));
#1066=LINE('',#1065,#1064);
#1067=CARTESIAN_POINT('',(60.,18.,36.));
#1068=VERTEX_POINT('',#1067);
#1069=EDGE_CURVE('P1_E548',#1068,#849,#1066,.F.);
#1070=ORIENTED_EDGE('',*,*,#1069,.F.);
#1071=DIRECTION('',(0.707106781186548,0.,-0.707106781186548));
#1072=VECTOR('',#1071,1.);
#1073=CARTESIAN_POINT('',(56.,18.,40.));
#1074=LINE('',#1073,#1072);
#1075=EDGE_CURVE('P1_E573',#1042,#1068,#1074,.T.);
#1076=ORIENTED_EDGE('',*,*,#1075,.F.);
#1077=EDGE_LOOP('',(#1061,#1062,#1070,#1076));
#1078=FACE_BOUND('',#1077,.T.);
#1079=ADVANCED_FACE('P1_F460',(#1078),#1060,.T.);
#1080=CARTESIAN_POINT('',(60.,0.,40.));
#1081=DIRECTION('',(1.,0.,0.));
#1082=DIRECTION('',(0.,0.,-1.));
#1083=AXIS2_PLACEMENT_3D('',#1080,#1081,#1082);
#1084=PLANE('',#1083);
#1085=DIRECTION('',(0.,0.,1.));
#1086=VECTOR('',#1085,1.);
#1087=CARTESIAN_POINT('',(60.,18.,0.));
#1088=LINE('',#1087,#1086);
#1089=CARTESIAN_POINT('',(60.,18.,-36.));
#1090=VERTEX_POINT('',#1089);
#1091=EDGE_CURVE('P1_E578',#1068,#1090,#1088,.F.);
#1092=ORIENTED_EDGE('',*,*,#1091,.F.);
#1093=ORIENTED_EDGE('',*,*,#1069,.T.);
#1094=ORIENTED_EDGE('',*,*,#850,.T.);
#1095=DIRECTION('',(0.,1.,0.));
#1096=VECTOR('',#1095,1.);
#1097=CARTESIAN_POINT('',(60.,10.5,-36.));
#1098=LINE('',#1097,#1096);
#1099=EDGE_CURVE('P1_E545',#1090,#841,#1098,.F.);
#1100=ORIENTED_EDGE('',*,*,#1099,.F.);
#1101=EDGE_LOOP('',(#1092,#1093,#1094,#1100));
#1102=FACE_BOUND('',#1101,.T.);
#1103=ADVANCED_FACE('P1_F456',(#1102),#1084,.T.);
#1104=CARTESIAN_POINT('',(58.,10.5,-38.));
#1105=DIRECTION('',(0.707106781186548,0.,-0.707106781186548));
#1106=DIRECTION('',(-0.707106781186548,0.,-0.707106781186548));
#1107=AXIS2_PLACEMENT_3D('',#1104,#1105,#1106);
#1108=PLANE('',#1107);
#1109=ORIENTED_EDGE('',*,*,#1099,.T.);
#1110=ORIENTED_EDGE('',*,*,#842,.T.);
#1111=DIRECTION('',(0.,1.,0.));
#1112=VECTOR('',#1111,1.);
#1113=CARTESIAN_POINT('',(56.,0.,-40.));
#1114=LINE('',#1113,#1112);
#1115=CARTESIAN_POINT('',(56.,18.,-40.));
#1116=VERTEX_POINT('',#1115);
#1117=EDGE_CURVE('P1_E540',#1116,#833,#1114,.F.);
#1118=ORIENTED_EDGE('',*,*,#1117,.F.);
#1119=DIRECTION('',(-0.707106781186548,0.,-0.707106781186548));
#1120=VECTOR('',#1119,1.);
#1121=CARTESIAN_POINT('',(60.,18.,-36.));
#1122=LINE('',#1121,#1120);
#1123=EDGE_CURVE('P1_E581',#1090,#1116,#1122,.T.);
#1124=ORIENTED_EDGE('',*,*,#1123,.F.);
#1125=EDGE_LOOP('',(#1109,#1110,#1118,#1124));
#1126=FACE_BOUND('',#1125,.T.);
#1127=ADVANCED_FACE('P1_F453',(#1126),#1108,.T.);
#1128=CARTESIAN_POINT('',(60.,0.,-40.));
#1129=DIRECTION('',(0.,0.,-1.));
#1130=DIRECTION('',(-1.,0.,0.));
#1131=AXIS2_PLACEMENT_3D('',#1128,#1129,#1130);
#1132=PLANE('',#1131);
#1133=ORIENTED_EDGE('',*,*,#834,.T.);
#1134=DIRECTION('',(0.,1.,0.));
#1135=VECTOR('',#1134,1.);
#1136=CARTESIAN_POINT('',(-56.,10.5,-40.));
#1137=LINE('',#1136,#1135);
#1138=CARTESIAN_POINT('',(-56.,18.,-40.));
#1139=VERTEX_POINT('',#1138);
#1140=EDGE_CURVE('P1_E35',#1139,#825,#1137,.F.);
#1141=ORIENTED_EDGE('',*,*,#1140,.F.);
#1142=DIRECTION('',(1.,0.,0.));
#1143=VECTOR('',#1142,1.);
#1144=CARTESIAN_POINT('',(0.,18.,-40.));
#1145=LINE('',#1144,#1143);
#1146=EDGE_CURVE('P1_E584',#1116,#1139,#1145,.F.);
#1147=ORIENTED_EDGE('',*,*,#1146,.F.);
#1148=ORIENTED_EDGE('',*,*,#1117,.T.);
#1149=EDGE_LOOP('',(#1133,#1141,#1147,#1148));
#1150=FACE_BOUND('',#1149,.T.);
#1151=ADVANCED_FACE('P1_F449',(#1150),#1132,.T.);
#1152=CARTESIAN_POINT('',(-58.,10.5,-38.));
#1153=DIRECTION('',(-0.707106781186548,0.,-0.707106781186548));
#1154=DIRECTION('',(-0.707106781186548,0.,0.707106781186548));
#1155=AXIS2_PLACEMENT_3D('',#1152,#1153,#1154);
#1156=PLANE('',#1155);
#1157=ORIENTED_EDGE('',*,*,#1140,.T.);
#1158=ORIENTED_EDGE('',*,*,#826,.T.);
#1159=ORIENTED_EDGE('',*,*,#996,.T.);
#1160=DIRECTION('',(-0.707106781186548,0.,0.707106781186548));
#1161=VECTOR('',#1160,1.);
#1162=CARTESIAN_POINT('',(-56.,18.,-40.));
#1163=LINE('',#1162,#1161);
#1164=EDGE_CURVE('P1_E322',#1139,#987,#1163,.T.);
#1165=ORIENTED_EDGE('',*,*,#1164,.F.);
#1166=EDGE_LOOP('',(#1157,#1158,#1159,#1165));
#1167=FACE_BOUND('',#1166,.T.);
#1168=ADVANCED_FACE('P1_F445',(#1167),#1156,.T.);
#1169=CARTESIAN_POINT('',(-50.,18.,26.));
#1170=DIRECTION('',(0.,1.,0.));
#1171=DIRECTION('',(0.,0.,1.));
#1172=AXIS2_PLACEMENT_3D('',#1169,#1170,#1171);
#1173=CYLINDRICAL_SURFACE('',#1172,5.5);
#1174=CARTESIAN_POINT('',(-50.,18.,26.));
#1175=DIRECTION('',(0.,1.,0.));
#1176=DIRECTION('',(0.,0.,1.));
#1177=AXIS2_PLACEMENT_3D('',#1174,#1175,#1176);
#1178=CIRCLE('',#1177,5.5);
#1179=CARTESIAN_POINT('',(-50.,18.,31.5));
#1180=VERTEX_POINT('',#1179);
#1181=EDGE_CURVE('P1_E319',#1180,#1180,#1178,.F.);
#1182=ORIENTED_EDGE('',*,*,#1181,.F.);
#1183=EDGE_LOOP('',(#1182));
#1184=FACE_BOUND('',#1183,.T.);
#1185=ORIENTED_EDGE('',*,*,#889,.F.);
#1186=EDGE_LOOP('',(#1185));
#1187=FACE_BOUND('',#1186,.T.);
#1188=ADVANCED_FACE('P1_F441',(#1184,#1187),#1173,.F.);
#1189=CARTESIAN_POINT('',(50.,18.,-26.));
#1190=DIRECTION('',(0.,1.,0.));
#1191=DIRECTION('',(0.,0.,1.));
#1192=AXIS2_PLACEMENT_3D('',#1189,#1190,#1191);
#1193=CYLINDRICAL_SURFACE('',#1192,5.5);
#1194=CARTESIAN_POINT('',(50.,18.,-26.));
#1195=DIRECTION('',(0.,1.,0.));
#1196=DIRECTION('',(0.,0.,1.));
#1197=AXIS2_PLACEMENT_3D('',#1194,#1195,#1196);
#1198=CIRCLE('',#1197,5.5);
#1199=CARTESIAN_POINT('',(50.,18.,-20.5));
#1200=VERTEX_POINT('',#1199);
#1201=EDGE_CURVE('P1_E316',#1200,#1200,#1198,.F.);
#1202=ORIENTED_EDGE('',*,*,#1201,.F.);
#1203=EDGE_LOOP('',(#1202));
#1204=FACE_BOUND('',#1203,.T.);
#1205=ORIENTED_EDGE('',*,*,#909,.F.);
#1206=EDGE_LOOP('',(#1205));
#1207=FACE_BOUND('',#1206,.T.);
#1208=ADVANCED_FACE('P1_F437',(#1204,#1207),#1193,.F.);
#1209=CARTESIAN_POINT('',(-50.,18.,-26.));
#1210=DIRECTION('',(0.,1.,0.));
#1211=DIRECTION('',(0.,0.,1.));
#1212=AXIS2_PLACEMENT_3D('',#1209,#1210,#1211);
#1213=CYLINDRICAL_SURFACE('',#1212,5.5);
#1214=CARTESIAN_POINT('',(-50.,18.,-26.));
#1215=DIRECTION('',(0.,1.,0.));
#1216=DIRECTION('',(0.,0.,1.));
#1217=AXIS2_PLACEMENT_3D('',#1214,#1215,#1216);
#1218=CIRCLE('',#1217,5.5);
#1219=CARTESIAN_POINT('',(-50.,18.,-20.5));
#1220=VERTEX_POINT('',#1219);
#1221=EDGE_CURVE('P1_E313',#1220,#1220,#1218,.F.);
#1222=ORIENTED_EDGE('',*,*,#1221,.F.);
#1223=EDGE_LOOP('',(#1222));
#1224=FACE_BOUND('',#1223,.T.);
#1225=ORIENTED_EDGE('',*,*,#929,.F.);
#1226=EDGE_LOOP('',(#1225));
#1227=FACE_BOUND('',#1226,.T.);
#1228=ADVANCED_FACE('P1_F433',(#1224,#1227),#1213,.F.);
#1229=CARTESIAN_POINT('',(50.,18.,26.));
#1230=DIRECTION('',(0.,1.,0.));
#1231=DIRECTION('',(0.,0.,1.));
#1232=AXIS2_PLACEMENT_3D('',#1229,#1230,#1231);
#1233=CYLINDRICAL_SURFACE('',#1232,5.5);
#1234=CARTESIAN_POINT('',(50.,18.,26.));
#1235=DIRECTION('',(0.,1.,0.));
#1236=DIRECTION('',(0.,0.,1.));
#1237=AXIS2_PLACEMENT_3D('',#1234,#1235,#1236);
#1238=CIRCLE('',#1237,5.5);
#1239=CARTESIAN_POINT('',(50.,18.,31.5));
#1240=VERTEX_POINT('',#1239);
#1241=EDGE_CURVE('P1_E26',#1240,#1240,#1238,.F.);
#1242=ORIENTED_EDGE('',*,*,#1241,.F.);
#1243=EDGE_LOOP('',(#1242));
#1244=FACE_BOUND('',#1243,.T.);
#1245=ORIENTED_EDGE('',*,*,#949,.F.);
#1246=EDGE_LOOP('',(#1245));
#1247=FACE_BOUND('',#1246,.T.);
#1248=ADVANCED_FACE('P1_F426',(#1244,#1247),#1233,.F.);
#1249=CARTESIAN_POINT('',(0.,18.,-6.69603261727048E-13));
#1250=DIRECTION('',(0.,1.,0.));
#1251=DIRECTION('',(0.,0.,1.));
#1252=AXIS2_PLACEMENT_3D('',#1249,#1250,#1251);
#1253=CONICAL_SURFACE('',#1252,33.2,0.785398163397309);
#1254=ORIENTED_EDGE('',*,*,#969,.F.);
#1255=EDGE_LOOP('',(#1254));
#1256=FACE_BOUND('',#1255,.T.);
#1257=CARTESIAN_POINT('',(0.,18.,0.));
#1258=DIRECTION('',(0.,1.,0.));
#1259=DIRECTION('',(0.,0.,1.));
#1260=AXIS2_PLACEMENT_3D('',#1257,#1258,#1259);
#1261=CIRCLE('',#1260,33.2);
#1262=CARTESIAN_POINT('',(0.,18.,33.2));
#1263=VERTEX_POINT('',#1262);
#1264=EDGE_CURVE('P1_E11',#1263,#1263,#1261,.F.);
#1265=ORIENTED_EDGE('',*,*,#1264,.F.);
#1266=EDGE_LOOP('',(#1265));
#1267=FACE_BOUND('',#1266,.T.);
#1268=ADVANCED_FACE('P1_F420',(#1256,#1267),#1253,.F.);
#1269=CARTESIAN_POINT('',(0.,18.,0.));
#1270=DIRECTION('',(0.,1.,0.));
#1271=DIRECTION('',(0.,0.,1.));
#1272=AXIS2_PLACEMENT_3D('',#1269,#1270,#1271);
#1273=PLANE('',#1272);
#1274=ORIENTED_EDGE('',*,*,#1264,.T.);
#1275=EDGE_LOOP('',(#1274));
#1276=FACE_BOUND('',#1275,.T.);
#1277=ORIENTED_EDGE('',*,*,#1241,.T.);
#1278=EDGE_LOOP('',(#1277));
#1279=FACE_BOUND('',#1278,.T.);
#1280=ORIENTED_EDGE('',*,*,#1221,.T.);
#1281=EDGE_LOOP('',(#1280));
#1282=FACE_BOUND('',#1281,.T.);
#1283=ORIENTED_EDGE('',*,*,#1201,.T.);
#1284=EDGE_LOOP('',(#1283));
#1285=FACE_BOUND('',#1284,.T.);
#1286=ORIENTED_EDGE('',*,*,#1181,.T.);
#1287=EDGE_LOOP('',(#1286));
#1288=FACE_BOUND('',#1287,.T.);
#1289=ORIENTED_EDGE('',*,*,#1146,.T.);
#1290=ORIENTED_EDGE('',*,*,#1164,.T.);
#1291=ORIENTED_EDGE('',*,*,#990,.T.);
#1292=ORIENTED_EDGE('',*,*,#1027,.T.);
#1293=ORIENTED_EDGE('',*,*,#1043,.T.);
#1294=ORIENTED_EDGE('',*,*,#1075,.T.);
#1295=ORIENTED_EDGE('',*,*,#1091,.T.);
#1296=ORIENTED_EDGE('',*,*,#1123,.T.);
#1297=EDGE_LOOP('',(#1289,#1290,#1291,#1292,#1293,#1294,#1295,#1296));
#1298=FACE_BOUND('',#1297,.T.);
#1299=ADVANCED_FACE('P1_F418',(#1276,#1279,#1282,#1285,#1288,#1298),#1273,.T.);
#1300=CLOSED_SHELL('',(#131,#160,#180,#210,#230,#251,#271,#292,#313,#334,#355,#375,#395,#415,
#435,#455,#475,#495,#515,#547,#567,#587,#607,#636,#656,#684,#712,#740,#768,#789,#876,#896,#916,
#936,#956,#976,#1007,#1031,#1055,#1079,#1103,#1127,#1151,#1168,#1188,#1208,#1228,#1248,#1268,#1299));
#1301=MANIFOLD_SOLID_BREP('P1_B1',#1300);
#1302=CARTESIAN_POINT('',(0.,4.386370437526,25.5));
#1303=DIRECTION('',(0.,1.,0.));
#1304=DIRECTION('',(0.,0.,1.));
#1305=AXIS2_PLACEMENT_3D('',#1302,#1303,#1304);
#1306=CYLINDRICAL_SURFACE('',#1305,1.5);
#1307=CARTESIAN_POINT('',(0.,7.,25.5));
#1308=DIRECTION('',(0.,1.,0.));
#1309=DIRECTION('',(0.,0.,1.));
#1310=AXIS2_PLACEMENT_3D('',#1307,#1308,#1309);
#1311=CIRCLE('',#1310,1.5);
#1312=CARTESIAN_POINT('',(0.,7.,27.));
#1313=VERTEX_POINT('',#1312);
#1314=EDGE_CURVE('P2_E11',#1313,#1313,#1311,.T.);
#1315=ORIENTED_EDGE('',*,*,#1314,.T.);
#1316=EDGE_LOOP('',(#1315));
#1317=FACE_BOUND('',#1316,.T.);
#1318=CARTESIAN_POINT('',(0.,12.,25.5));
#1319=DIRECTION('',(0.,1.,0.));
#1320=DIRECTION('',(0.,0.,1.));
#1321=AXIS2_PLACEMENT_3D('',#1318,#1319,#1320);
#1322=CIRCLE('',#1321,1.5);
#1323=CARTESIAN_POINT('',(0.,12.,27.));
#1324=VERTEX_POINT('',#1323);
#1325=EDGE_CURVE('P2_E23',#1324,#1324,#1322,.F.);
#1326=ORIENTED_EDGE('',*,*,#1325,.T.);
#1327=EDGE_LOOP('',(#1326));
#1328=FACE_BOUND('',#1327,.T.);
#1329=ADVANCED_FACE('P2_F16',(#1317,#1328),#1306,.T.);
#1330=CARTESIAN_POINT('',(0.,7.,25.5));
#1331=DIRECTION('',(0.,1.,0.));
#1332=DIRECTION('',(0.,0.,1.));
#1333=AXIS2_PLACEMENT_3D('',#1330,#1331,#1332);
#1334=PLANE('',#1333);
#1335=CARTESIAN_POINT('',(0.,7.,24.25));
#1336=CARTESIAN_POINT('',(0.238673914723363,7.,24.2502025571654));
#1337=CARTESIAN_POINT('',(0.460118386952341,7.,24.337764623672));
#1338=CARTESIAN_POINT('',(0.700373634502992,7.,24.4327647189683));
#1339=CARTESIAN_POINT('',(0.883883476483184,7.,24.6161165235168));
#1340=CARTESIAN_POINT('',(1.06664780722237,7.,24.7987234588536));
#1341=CARTESIAN_POINT('',(1.16223537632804,7.,25.0398816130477));
#1342=CARTESIAN_POINT('',(1.24989860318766,7.,25.2610474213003));
#1343=CARTESIAN_POINT('',(1.25,7.,25.5));
#1344=CARTESIAN_POINT('',(1.25010095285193,7.,25.7379063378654));
#1345=CARTESIAN_POINT('',(1.16223537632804,7.,25.9601183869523));
#1346=CARTESIAN_POINT('',(1.06723528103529,7.,26.2003736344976));
#1347=CARTESIAN_POINT('',(0.883883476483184,7.,26.3838834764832));
#1348=CARTESIAN_POINT('',(0.701276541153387,7.,26.5666478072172));
#1349=CARTESIAN_POINT('',(0.460118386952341,7.,26.662235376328));
#1350=CARTESIAN_POINT('',(0.239208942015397,7.,26.7497969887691));
#1351=CARTESIAN_POINT('',(0.,7.,26.75));
#1352=B_SPLINE_CURVE_WITH_KNOTS('',2,(#1335,#1336,#1337,#1338,#1339,#1340,#1341,#1342,#1343,
#1344,#1345,#1346,#1347,#1348,#1349,#1350,#1351),.UNSPECIFIED.,.F.,.F.,(3,2,2,2,2,2,2,2,3),(0.,
0.125,0.25,0.375,0.5,0.625,0.75,0.875,1.),.UNSPECIFIED.);
#1353=CARTESIAN_POINT('',(0.,7.,24.25));
#1354=VERTEX_POINT('',#1353);
#1355=CARTESIAN_POINT('',(0.,7.,26.75));
#1356=VERTEX_POINT('',#1355);
#1357=EDGE_CURVE('P2_E27',#1354,#1356,#1352,.T.);
#1358=ORIENTED_EDGE('',*,*,#1357,.F.);
#1359=CARTESIAN_POINT('',(0.,7.,26.75));
#1360=CARTESIAN_POINT('',(-0.238673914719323,7.,26.7497974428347));
#1361=CARTESIAN_POINT('',(-0.460118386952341,7.,26.662235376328));
#1362=CARTESIAN_POINT('',(-0.700373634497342,7.,26.5672352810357));
#1363=CARTESIAN_POINT('',(-0.883883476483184,7.,26.3838834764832));
#1364=CARTESIAN_POINT('',(-1.06664780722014,7.,26.2012765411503));
#1365=CARTESIAN_POINT('',(-1.16223537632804,7.,25.9601183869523));
#1366=CARTESIAN_POINT('',(-1.24989860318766,7.,25.7389525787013));
#1367=CARTESIAN_POINT('',(-1.25,7.,25.5));
#1368=CARTESIAN_POINT('',(-1.25010095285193,7.,25.2620936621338));
#1369=CARTESIAN_POINT('',(-1.16223537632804,7.,25.0398816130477));
#1370=CARTESIAN_POINT('',(-1.06723528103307,7.,24.7996263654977));
#1371=CARTESIAN_POINT('',(-0.883883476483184,7.,24.6161165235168));
#1372=CARTESIAN_POINT('',(-0.701276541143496,7.,24.4333521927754));
#1373=CARTESIAN_POINT('',(-0.460118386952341,7.,24.337764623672));
#1374=CARTESIAN_POINT('',(-0.239208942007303,7.,24.2502030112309));
#1375=CARTESIAN_POINT('',(0.,7.,24.25));
#1376=B_SPLINE_CURVE_WITH_KNOTS('',2,(#1359,#1360,#1361,#1362,#1363,#1364,#1365,#1366,#1367,
#1368,#1369,#1370,#1371,#1372,#1373,#1374,#1375),.UNSPECIFIED.,.F.,.F.,(3,2,2,2,2,2,2,2,3),(0.,
0.125,0.25,0.375,0.5,0.625,0.75,0.875,1.),.UNSPECIFIED.);
#1377=EDGE_CURVE('P2_E32',#1356,#1354,#1376,.T.);
#1378=ORIENTED_EDGE('',*,*,#1377,.F.);
#1379=EDGE_LOOP('',(#1358,#1378));
#1380=FACE_BOUND('',#1379,.T.);
#1381=ORIENTED_EDGE('',*,*,#1314,.F.);
#1382=EDGE_LOOP('',(#1381));
#1383=FACE_BOUND('',#1382,.T.);
#1384=ADVANCED_FACE('P2_F17',(#1380,#1383),#1334,.F.);
#1385=OPEN_SHELL('',(#1329,#1384));
#1386=SHELL_BASED_SURFACE_MODEL('P2_B1',(#1385));
#1387=CARTESIAN_POINT('',(-25.5,4.386370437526,0.));
#1388=DIRECTION('',(0.,1.,0.));
#1389=DIRECTION('',(0.,0.,1.));
#1390=AXIS2_PLACEMENT_3D('',#1387,#1388,#1389);
#1391=CYLINDRICAL_SURFACE('',#1390,1.5);
#1392=CARTESIAN_POINT('',(-25.5,7.,0.));
#1393=DIRECTION('',(0.,1.,0.));
#1394=DIRECTION('',(0.,0.,1.));
#1395=AXIS2_PLACEMENT_3D('',#1392,#1393,#1394);
#1396=CIRCLE('',#1395,1.5);
#1397=CARTESIAN_POINT('',(-25.5,7.,1.5));
#1398=VERTEX_POINT('',#1397);
#1399=EDGE_CURVE('P3_E11',#1398,#1398,#1396,.T.);
#1400=ORIENTED_EDGE('',*,*,#1399,.T.);
#1401=EDGE_LOOP('',(#1400));
#1402=FACE_BOUND('',#1401,.T.);
#1403=CARTESIAN_POINT('',(-25.5,12.,0.));
#1404=DIRECTION('',(0.,1.,0.));
#1405=DIRECTION('',(0.,0.,1.));
#1406=AXIS2_PLACEMENT_3D('',#1403,#1404,#1405);
#1407=CIRCLE('',#1406,1.5);
#1408=CARTESIAN_POINT('',(-25.5,12.,1.5));
#1409=VERTEX_POINT('',#1408);
#1410=EDGE_CURVE('P3_E23',#1409,#1409,#1407,.F.);
#1411=ORIENTED_EDGE('',*,*,#1410,.T.);
#1412=EDGE_LOOP('',(#1411));
#1413=FACE_BOUND('',#1412,.T.);
#1414=ADVANCED_FACE('P3_F16',(#1402,#1413),#1391,.T.);
#1415=CARTESIAN_POINT('',(-25.5,7.,0.));
#1416=DIRECTION('',(0.,1.,0.));
#1417=DIRECTION('',(0.,0.,1.));
#1418=AXIS2_PLACEMENT_3D('',#1415,#1416,#1417);
#1419=PLANE('',#1418);
#1420=CARTESIAN_POINT('',(-24.25,7.,0.));
#1421=CARTESIAN_POINT('',(-24.2502025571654,7.,0.238673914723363));
#1422=CARTESIAN_POINT('',(-24.337764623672,7.,0.460118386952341));
#1423=CARTESIAN_POINT('',(-24.4327647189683,7.,0.700373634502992));
#1424=CARTESIAN_POINT('',(-24.6161165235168,7.,0.883883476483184));
#1425=CARTESIAN_POINT('',(-24.7987234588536,7.,1.06664780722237));
#1426=CARTESIAN_POINT('',(-25.0398816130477,7.,1.16223537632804));
#1427=CARTESIAN_POINT('',(-25.2610474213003,7.,1.24989860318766));
#1428=CARTESIAN_POINT('',(-25.5,7.,1.25));
#1429=CARTESIAN_POINT('',(-25.7379063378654,7.,1.25010095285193));
#1430=CARTESIAN_POINT('',(-25.9601183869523,7.,1.16223537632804));
#1431=CARTESIAN_POINT('',(-26.2003736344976,7.,1.06723528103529));
#1432=CARTESIAN_POINT('',(-26.3838834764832,7.,0.883883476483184));
#1433=CARTESIAN_POINT('',(-26.5666478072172,7.,0.701276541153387));
#1434=CARTESIAN_POINT('',(-26.662235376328,7.,0.460118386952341));
#1435=CARTESIAN_POINT('',(-26.7497969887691,7.,0.239208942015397));
#1436=CARTESIAN_POINT('',(-26.75,7.,0.));
#1437=B_SPLINE_CURVE_WITH_KNOTS('',2,(#1420,#1421,#1422,#1423,#1424,#1425,#1426,#1427,#1428,
#1429,#1430,#1431,#1432,#1433,#1434,#1435,#1436),.UNSPECIFIED.,.F.,.F.,(3,2,2,2,2,2,2,2,3),(0.,
0.125,0.25,0.375,0.5,0.625,0.75,0.875,1.),.UNSPECIFIED.);
#1438=CARTESIAN_POINT('',(-24.25,7.,0.));
#1439=VERTEX_POINT('',#1438);
#1440=CARTESIAN_POINT('',(-26.75,7.,0.));
#1441=VERTEX_POINT('',#1440);
#1442=EDGE_CURVE('P3_E27',#1439,#1441,#1437,.T.);
#1443=ORIENTED_EDGE('',*,*,#1442,.F.);
#1444=CARTESIAN_POINT('',(-26.75,7.,0.));
#1445=CARTESIAN_POINT('',(-26.7497974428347,7.,-0.238673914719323));
#1446=CARTESIAN_POINT('',(-26.662235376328,7.,-0.460118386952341));
#1447=CARTESIAN_POINT('',(-26.5672352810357,7.,-0.700373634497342));
#1448=CARTESIAN_POINT('',(-26.3838834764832,7.,-0.883883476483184));
#1449=CARTESIAN_POINT('',(-26.2012765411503,7.,-1.06664780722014));
#1450=CARTESIAN_POINT('',(-25.9601183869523,7.,-1.16223537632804));
#1451=CARTESIAN_POINT('',(-25.7389525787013,7.,-1.24989860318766));
#1452=CARTESIAN_POINT('',(-25.5,7.,-1.25));
#1453=CARTESIAN_POINT('',(-25.2620936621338,7.,-1.25010095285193));
#1454=CARTESIAN_POINT('',(-25.0398816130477,7.,-1.16223537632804));
#1455=CARTESIAN_POINT('',(-24.7996263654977,7.,-1.06723528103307));
#1456=CARTESIAN_POINT('',(-24.6161165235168,7.,-0.883883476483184));
#1457=CARTESIAN_POINT('',(-24.4333521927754,7.,-0.701276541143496));
#1458=CARTESIAN_POINT('',(-24.337764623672,7.,-0.460118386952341));
#1459=CARTESIAN_POINT('',(-24.2502030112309,7.,-0.239208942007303));
#1460=CARTESIAN_POINT('',(-24.25,7.,0.));
#1461=B_SPLINE_CURVE_WITH_KNOTS('',2,(#1444,#1445,#1446,#1447,#1448,#1449,#1450,#1451,#1452,
#1453,#1454,#1455,#1456,#1457,#1458,#1459,#1460),.UNSPECIFIED.,.F.,.F.,(3,2,2,2,2,2,2,2,3),(0.,
0.125,0.25,0.375,0.5,0.625,0.75,0.875,1.),.UNSPECIFIED.);
#1462=EDGE_CURVE('P3_E32',#1441,#1439,#1461,.T.);
#1463=ORIENTED_EDGE('',*,*,#1462,.F.);
#1464=EDGE_LOOP('',(#1443,#1463));
#1465=FACE_BOUND('',#1464,.T.);
#1466=ORIENTED_EDGE('',*,*,#1399,.F.);
#1467=EDGE_LOOP('',(#1466));
#1468=FACE_BOUND('',#1467,.T.);
#1469=ADVANCED_FACE('P3_F17',(#1465,#1468),#1419,.F.);
#1470=OPEN_SHELL('',(#1414,#1469));
#1471=SHELL_BASED_SURFACE_MODEL('P3_B1',(#1470));
#1472=CARTESIAN_POINT('',(0.,4.386370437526,-25.5));
#1473=DIRECTION('',(0.,1.,0.));
#1474=DIRECTION('',(0.,0.,1.));
#1475=AXIS2_PLACEMENT_3D('',#1472,#1473,#1474);
#1476=CYLINDRICAL_SURFACE('',#1475,1.5);
#1477=CARTESIAN_POINT('',(0.,7.,-25.5));
#1478=DIRECTION('',(0.,1.,0.));
#1479=DIRECTION('',(0.,0.,1.));
#1480=AXIS2_PLACEMENT_3D('',#1477,#1478,#1479);
#1481=CIRCLE('',#1480,1.5);
#1482=CARTESIAN_POINT('',(0.,7.,-24.));
#1483=VERTEX_POINT('',#1482);
#1484=EDGE_CURVE('P4_E11',#1483,#1483,#1481,.T.);
#1485=ORIENTED_EDGE('',*,*,#1484,.T.);
#1486=EDGE_LOOP('',(#1485));
#1487=FACE_BOUND('',#1486,.T.);
#1488=CARTESIAN_POINT('',(0.,12.,-25.5));
#1489=DIRECTION('',(0.,1.,0.));
#1490=DIRECTION('',(0.,0.,1.));
#1491=AXIS2_PLACEMENT_3D('',#1488,#1489,#1490);
#1492=CIRCLE('',#1491,1.5);
#1493=CARTESIAN_POINT('',(0.,12.,-24.));
#1494=VERTEX_POINT('',#1493);
#1495=EDGE_CURVE('P4_E23',#1494,#1494,#1492,.F.);
#1496=ORIENTED_EDGE('',*,*,#1495,.T.);
#1497=EDGE_LOOP('',(#1496));
#1498=FACE_BOUND('',#1497,.T.);
#1499=ADVANCED_FACE('P4_F16',(#1487,#1498),#1476,.T.);
#1500=CARTESIAN_POINT('',(0.,7.,-25.5));
#1501=DIRECTION('',(0.,1.,0.));
#1502=DIRECTION('',(0.,0.,1.));
#1503=AXIS2_PLACEMENT_3D('',#1500,#1501,#1502);
#1504=PLANE('',#1503);
#1505=CARTESIAN_POINT('',(0.,7.,-24.25));
#1506=CARTESIAN_POINT('',(-0.238673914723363,7.,-24.2502025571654));
#1507=CARTESIAN_POINT('',(-0.460118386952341,7.,-24.337764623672));
#1508=CARTESIAN_POINT('',(-0.700373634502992,7.,-24.4327647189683));
#1509=CARTESIAN_POINT('',(-0.883883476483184,7.,-24.6161165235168));
#1510=CARTESIAN_POINT('',(-1.06664780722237,7.,-24.7987234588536));
#1511=CARTESIAN_POINT('',(-1.16223537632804,7.,-25.0398816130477));
#1512=CARTESIAN_POINT('',(-1.24989860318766,7.,-25.2610474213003));
#1513=CARTESIAN_POINT('',(-1.25,7.,-25.5));
#1514=CARTESIAN_POINT('',(-1.25010095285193,7.,-25.7379063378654));
#1515=CARTESIAN_POINT('',(-1.16223537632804,7.,-25.9601183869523));
#1516=CARTESIAN_POINT('',(-1.06723528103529,7.,-26.2003736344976));
#1517=CARTESIAN_POINT('',(-0.883883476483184,7.,-26.3838834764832));
#1518=CARTESIAN_POINT('',(-0.701276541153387,7.,-26.5666478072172));
#1519=CARTESIAN_POINT('',(-0.460118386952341,7.,-26.662235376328));
#1520=CARTESIAN_POINT('',(-0.239208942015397,7.,-26.7497969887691));
#1521=CARTESIAN_POINT('',(0.,7.,-26.75));
#1522=B_SPLINE_CURVE_WITH_KNOTS('',2,(#1505,#1506,#1507,#1508,#1509,#1510,#1511,#1512,#1513,
#1514,#1515,#1516,#1517,#1518,#1519,#1520,#1521),.UNSPECIFIED.,.F.,.F.,(3,2,2,2,2,2,2,2,3),(0.,
0.125,0.25,0.375,0.5,0.625,0.75,0.875,1.),.UNSPECIFIED.);
#1523=CARTESIAN_POINT('',(0.,7.,-24.25));
#1524=VERTEX_POINT('',#1523);
#1525=CARTESIAN_POINT('',(0.,7.,-26.75));
#1526=VERTEX_POINT('',#1525);
#1527=EDGE_CURVE('P4_E27',#1524,#1526,#1522,.T.);
#1528=ORIENTED_EDGE('',*,*,#1527,.F.);
#1529=CARTESIAN_POINT('',(0.,7.,-26.75));
#1530=CARTESIAN_POINT('',(0.238673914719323,7.,-26.7497974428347));
#1531=CARTESIAN_POINT('',(0.460118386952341,7.,-26.662235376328));
#1532=CARTESIAN_POINT('',(0.700373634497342,7.,-26.5672352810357));
#1533=CARTESIAN_POINT('',(0.883883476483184,7.,-26.3838834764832));
#1534=CARTESIAN_POINT('',(1.06664780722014,7.,-26.2012765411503));
#1535=CARTESIAN_POINT('',(1.16223537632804,7.,-25.9601183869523));
#1536=CARTESIAN_POINT('',(1.24989860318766,7.,-25.7389525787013));
#1537=CARTESIAN_POINT('',(1.25,7.,-25.5));
#1538=CARTESIAN_POINT('',(1.25010095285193,7.,-25.2620936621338));
#1539=CARTESIAN_POINT('',(1.16223537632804,7.,-25.0398816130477));
#1540=CARTESIAN_POINT('',(1.06723528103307,7.,-24.7996263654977));
#1541=CARTESIAN_POINT('',(0.883883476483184,7.,-24.6161165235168));
#1542=CARTESIAN_POINT('',(0.701276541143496,7.,-24.4333521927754));
#1543=CARTESIAN_POINT('',(0.460118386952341,7.,-24.337764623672));
#1544=CARTESIAN_POINT('',(0.239208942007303,7.,-24.2502030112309));
#1545=CARTESIAN_POINT('',(0.,7.,-24.25));
#1546=B_SPLINE_CURVE_WITH_KNOTS('',2,(#1529,#1530,#1531,#1532,#1533,#1534,#1535,#1536,#1537,
#1538,#1539,#1540,#1541,#1542,#1543,#1544,#1545),.UNSPECIFIED.,.F.,.F.,(3,2,2,2,2,2,2,2,3),(0.,
0.125,0.25,0.375,0.5,0.625,0.75,0.875,1.),.UNSPECIFIED.);
#1547=EDGE_CURVE('P4_E32',#1526,#1524,#1546,.T.);
#1548=ORIENTED_EDGE('',*,*,#1547,.F.);
#1549=EDGE_LOOP('',(#1528,#1548));
#1550=FACE_BOUND('',#1549,.T.);
#1551=ORIENTED_EDGE('',*,*,#1484,.F.);
#1552=EDGE_LOOP('',(#1551));
#1553=FACE_BOUND('',#1552,.T.);
#1554=ADVANCED_FACE('P4_F17',(#1550,#1553),#1504,.F.);
#1555=OPEN_SHELL('',(#1499,#1554));
#1556=SHELL_BASED_SURFACE_MODEL('P4_B1',(#1555));
#1557=ADVANCED_BREP_SHAPE_REPRESENTATION('',(#18,#1301),#14);
#1558=MANIFOLD_SURFACE_SHAPE_REPRESENTATION('',(#18,#103,#1386,#1471,#1556),#14);
#1559=SHAPE_REPRESENTATION('',(#18),#14);
#1560=SHAPE_DEFINITION_REPRESENTATION(#9,#1559);
#1561=SHAPE_REPRESENTATION_RELATIONSHIP('','',#1559,#1557);
#1562=SHAPE_REPRESENTATION_RELATIONSHIP('','',#1559,#1558);
ENDSEC;
END-ISO-10303-21;
